VERSION 5.8 ;
NAMESCASESENSITIVE ON ;
BUSBITCHARS "[]" ;
DIVIDERCHAR "/" ;
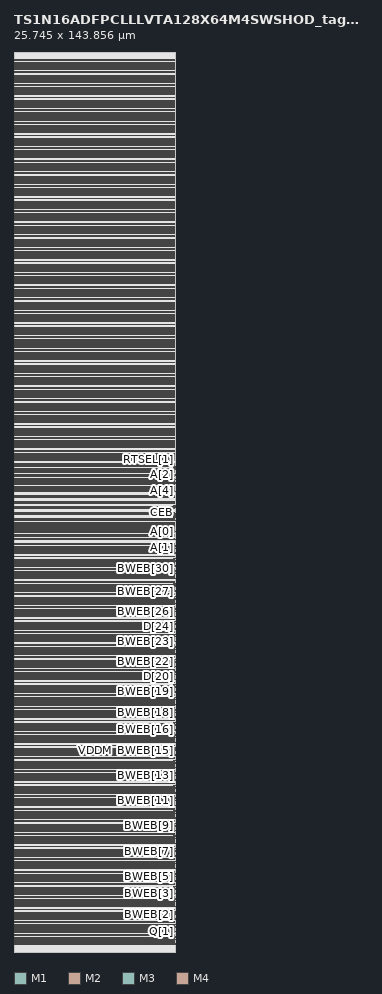
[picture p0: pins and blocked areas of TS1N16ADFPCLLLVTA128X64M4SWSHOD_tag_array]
MACRO TS1N16ADFPCLLLVTA128X64M4SWSHOD_tag_array
	CLASS BLOCK ;
	FOREIGN TS1N16ADFPCLLLVTA128X64M4SWSHOD_tag_array 0.0 0.0 ;
	ORIGIN 0.0 0.0 ;
	SIZE 25.745 BY 143.856 ;
	SYMMETRY X Y ;
	PIN A[0]
		DIRECTION INPUT ;
		USE SIGNAL ;
		PORT
			LAYER M1 ;
			RECT 25.497 67.208 25.745 67.288 ;
			LAYER M2 ;
			RECT 25.497 67.208 25.745 67.288 ;
			LAYER M3 ;
			RECT 25.497 67.208 25.745 67.288 ;
		END
	END A[0]

	PIN A[1]
		DIRECTION INPUT ;
		USE SIGNAL ;
		PORT
			LAYER M1 ;
			RECT 25.497 65.864 25.745 65.944 ;
			LAYER M2 ;
			RECT 25.497 65.864 25.745 65.944 ;
			LAYER M3 ;
			RECT 25.497 65.864 25.745 65.944 ;
		END
	END A[1]

	PIN A[2]
		DIRECTION INPUT ;
		USE SIGNAL ;
		PORT
			LAYER M1 ;
			RECT 25.497 76.232 25.745 76.312 ;
			LAYER M2 ;
			RECT 25.497 76.232 25.745 76.312 ;
			LAYER M3 ;
			RECT 25.497 76.232 25.745 76.312 ;
		END
	END A[2]

	PIN A[3]
		DIRECTION INPUT ;
		USE SIGNAL ;
		PORT
			LAYER M1 ;
			RECT 25.497 75.464 25.745 75.544 ;
			LAYER M2 ;
			RECT 25.497 75.464 25.745 75.544 ;
			LAYER M3 ;
			RECT 25.497 75.464 25.745 75.544 ;
		END
	END A[3]

	PIN A[4]
		DIRECTION INPUT ;
		USE SIGNAL ;
		PORT
			LAYER M1 ;
			RECT 25.497 74.888 25.745 74.968 ;
			LAYER M2 ;
			RECT 25.497 74.888 25.745 74.968 ;
			LAYER M3 ;
			RECT 25.497 74.888 25.745 74.968 ;
		END
	END A[4]



	PIN BWEB[0]
		DIRECTION INPUT ;
		USE SIGNAL ;
		PORT
			LAYER M1 ;
			RECT 25.497 1.976 25.745 2.056 ;
			LAYER M2 ;
			RECT 25.497 1.976 25.745 2.056 ;
			LAYER M3 ;
			RECT 25.497 1.976 25.745 2.056 ;
		END
	END BWEB[0]

	PIN BWEB[1]
		DIRECTION INPUT ;
		USE SIGNAL ;
		PORT
			LAYER M1 ;
			RECT 25.497 3.992 25.745 4.072 ;
			LAYER M2 ;
			RECT 25.497 3.992 25.745 4.072 ;
			LAYER M3 ;
			RECT 25.497 3.992 25.745 4.072 ;
		END
	END BWEB[1]

	PIN BWEB[2]
		DIRECTION INPUT ;
		USE SIGNAL ;
		PORT
			LAYER M1 ;
			RECT 25.497 6.008 25.745 6.088 ;
			LAYER M2 ;
			RECT 25.497 6.008 25.745 6.088 ;
			LAYER M3 ;
			RECT 25.497 6.008 25.745 6.088 ;
		END
	END BWEB[2]

	PIN BWEB[3]
		DIRECTION INPUT ;
		USE SIGNAL ;
		PORT
			LAYER M1 ;
			RECT 25.497 8.024 25.745 8.104 ;
			LAYER M2 ;
			RECT 25.497 8.024 25.745 8.104 ;
			LAYER M3 ;
			RECT 25.497 8.024 25.745 8.104 ;
		END
	END BWEB[3]

	PIN BWEB[4]
		DIRECTION INPUT ;
		USE SIGNAL ;
		PORT
			LAYER M1 ;
			RECT 25.497 10.040 25.745 10.120 ;
			LAYER M2 ;
			RECT 25.497 10.040 25.745 10.120 ;
			LAYER M3 ;
			RECT 25.497 10.040 25.745 10.120 ;
		END
	END BWEB[4]

	PIN BWEB[5]
		DIRECTION INPUT ;
		USE SIGNAL ;
		PORT
			LAYER M1 ;
			RECT 25.497 12.056 25.745 12.136 ;
			LAYER M2 ;
			RECT 25.497 12.056 25.745 12.136 ;
			LAYER M3 ;
			RECT 25.497 12.056 25.745 12.136 ;
		END
	END BWEB[5]

	PIN BWEB[6]
		DIRECTION INPUT ;
		USE SIGNAL ;
		PORT
			LAYER M1 ;
			RECT 25.497 14.072 25.745 14.152 ;
			LAYER M2 ;
			RECT 25.497 14.072 25.745 14.152 ;
			LAYER M3 ;
			RECT 25.497 14.072 25.745 14.152 ;
		END
	END BWEB[6]

	PIN BWEB[7]
		DIRECTION INPUT ;
		USE SIGNAL ;
		PORT
			LAYER M1 ;
			RECT 25.497 16.088 25.745 16.168 ;
			LAYER M2 ;
			RECT 25.497 16.088 25.745 16.168 ;
			LAYER M3 ;
			RECT 25.497 16.088 25.745 16.168 ;
		END
	END BWEB[7]

	PIN BWEB[8]
		DIRECTION INPUT ;
		USE SIGNAL ;
		PORT
			LAYER M1 ;
			RECT 25.497 18.104 25.745 18.184 ;
			LAYER M2 ;
			RECT 25.497 18.104 25.745 18.184 ;
			LAYER M3 ;
			RECT 25.497 18.104 25.745 18.184 ;
		END
	END BWEB[8]

	PIN BWEB[9]
		DIRECTION INPUT ;
		USE SIGNAL ;
		PORT
			LAYER M1 ;
			RECT 25.497 20.120 25.745 20.200 ;
			LAYER M2 ;
			RECT 25.497 20.120 25.745 20.200 ;
			LAYER M3 ;
			RECT 25.497 20.120 25.745 20.200 ;
		END
	END BWEB[9]

	PIN BWEB[10]
		DIRECTION INPUT ;
		USE SIGNAL ;
		PORT
			LAYER M1 ;
			RECT 25.497 22.136 25.745 22.216 ;
			LAYER M2 ;
			RECT 25.497 22.136 25.745 22.216 ;
			LAYER M3 ;
			RECT 25.497 22.136 25.745 22.216 ;
		END
	END BWEB[10]

	PIN BWEB[11]
		DIRECTION INPUT ;
		USE SIGNAL ;
		PORT
			LAYER M1 ;
			RECT 25.497 24.152 25.745 24.232 ;
			LAYER M2 ;
			RECT 25.497 24.152 25.745 24.232 ;
			LAYER M3 ;
			RECT 25.497 24.152 25.745 24.232 ;
		END
	END BWEB[11]

	PIN BWEB[12]
		DIRECTION INPUT ;
		USE SIGNAL ;
		PORT
			LAYER M1 ;
			RECT 25.497 26.168 25.745 26.248 ;
			LAYER M2 ;
			RECT 25.497 26.168 25.745 26.248 ;
			LAYER M3 ;
			RECT 25.497 26.168 25.745 26.248 ;
		END
	END BWEB[12]

	PIN BWEB[13]
		DIRECTION INPUT ;
		USE SIGNAL ;
		PORT
			LAYER M1 ;
			RECT 25.497 28.184 25.745 28.264 ;
			LAYER M2 ;
			RECT 25.497 28.184 25.745 28.264 ;
			LAYER M3 ;
			RECT 25.497 28.184 25.745 28.264 ;
		END
	END BWEB[13]

	PIN BWEB[14]
		DIRECTION INPUT ;
		USE SIGNAL ;
		PORT
			LAYER M1 ;
			RECT 25.497 30.200 25.745 30.280 ;
			LAYER M2 ;
			RECT 25.497 30.200 25.745 30.280 ;
			LAYER M3 ;
			RECT 25.497 30.200 25.745 30.280 ;
		END
	END BWEB[14]

	PIN BWEB[15]
		DIRECTION INPUT ;
		USE SIGNAL ;
		PORT
			LAYER M1 ;
			RECT 25.497 32.216 25.745 32.296 ;
			LAYER M2 ;
			RECT 25.497 32.216 25.745 32.296 ;
			LAYER M3 ;
			RECT 25.497 32.216 25.745 32.296 ;
		END
	END BWEB[15]

	PIN BWEB[16]
		DIRECTION INPUT ;
		USE SIGNAL ;
		PORT
			LAYER M1 ;
			RECT 25.497 34.232 25.745 34.312 ;
			LAYER M2 ;
			RECT 25.497 34.232 25.745 34.312 ;
			LAYER M3 ;
			RECT 25.497 34.232 25.745 34.312 ;
		END
	END BWEB[16]

	PIN BWEB[17]
		DIRECTION INPUT ;
		USE SIGNAL ;
		PORT
			LAYER M1 ;
			RECT 25.497 36.248 25.745 36.328 ;
			LAYER M2 ;
			RECT 25.497 36.248 25.745 36.328 ;
			LAYER M3 ;
			RECT 25.497 36.248 25.745 36.328 ;
		END
	END BWEB[17]

	PIN BWEB[18]
		DIRECTION INPUT ;
		USE SIGNAL ;
		PORT
			LAYER M1 ;
			RECT 25.497 38.264 25.745 38.344 ;
			LAYER M2 ;
			RECT 25.497 38.264 25.745 38.344 ;
			LAYER M3 ;
			RECT 25.497 38.264 25.745 38.344 ;
		END
	END BWEB[18]

	PIN BWEB[19]
		DIRECTION INPUT ;
		USE SIGNAL ;
		PORT
			LAYER M1 ;
			RECT 25.497 40.280 25.745 40.360 ;
			LAYER M2 ;
			RECT 25.497 40.280 25.745 40.360 ;
			LAYER M3 ;
			RECT 25.497 40.280 25.745 40.360 ;
		END
	END BWEB[19]

	PIN BWEB[20]
		DIRECTION INPUT ;
		USE SIGNAL ;
		PORT
			LAYER M1 ;
			RECT 25.497 42.296 25.745 42.376 ;
			LAYER M2 ;
			RECT 25.497 42.296 25.745 42.376 ;
			LAYER M3 ;
			RECT 25.497 42.296 25.745 42.376 ;
		END
	END BWEB[20]

	PIN BWEB[21]
		DIRECTION INPUT ;
		USE SIGNAL ;
		PORT
			LAYER M1 ;
			RECT 25.497 44.312 25.745 44.392 ;
			LAYER M2 ;
			RECT 25.497 44.312 25.745 44.392 ;
			LAYER M3 ;
			RECT 25.497 44.312 25.745 44.392 ;
		END
	END BWEB[21]

	PIN BWEB[22]
		DIRECTION INPUT ;
		USE SIGNAL ;
		PORT
			LAYER M1 ;
			RECT 25.497 46.328 25.745 46.408 ;
			LAYER M2 ;
			RECT 25.497 46.328 25.745 46.408 ;
			LAYER M3 ;
			RECT 25.497 46.328 25.745 46.408 ;
		END
	END BWEB[22]

	PIN BWEB[23]
		DIRECTION INPUT ;
		USE SIGNAL ;
		PORT
			LAYER M1 ;
			RECT 25.497 48.344 25.745 48.424 ;
			LAYER M2 ;
			RECT 25.497 48.344 25.745 48.424 ;
			LAYER M3 ;
			RECT 25.497 48.344 25.745 48.424 ;
		END
	END BWEB[23]

	PIN BWEB[24]
		DIRECTION INPUT ;
		USE SIGNAL ;
		PORT
			LAYER M1 ;
			RECT 25.497 50.360 25.745 50.440 ;
			LAYER M2 ;
			RECT 25.497 50.360 25.745 50.440 ;
			LAYER M3 ;
			RECT 25.497 50.360 25.745 50.440 ;
		END
	END BWEB[24]

	PIN BWEB[25]
		DIRECTION INPUT ;
		USE SIGNAL ;
		PORT
			LAYER M1 ;
			RECT 25.497 52.376 25.745 52.456 ;
			LAYER M2 ;
			RECT 25.497 52.376 25.745 52.456 ;
			LAYER M3 ;
			RECT 25.497 52.376 25.745 52.456 ;
		END
	END BWEB[25]

	PIN BWEB[26]
		DIRECTION INPUT ;
		USE SIGNAL ;
		PORT
			LAYER M1 ;
			RECT 25.497 54.392 25.745 54.472 ;
			LAYER M2 ;
			RECT 25.497 54.392 25.745 54.472 ;
			LAYER M3 ;
			RECT 25.497 54.392 25.745 54.472 ;
		END
	END BWEB[26]

	PIN BWEB[27]
		DIRECTION INPUT ;
		USE SIGNAL ;
		PORT
			LAYER M1 ;
			RECT 25.497 56.408 25.745 56.488 ;
			LAYER M2 ;
			RECT 25.497 56.408 25.745 56.488 ;
			LAYER M3 ;
			RECT 25.497 56.408 25.745 56.488 ;
		END
	END BWEB[27]

	PIN BWEB[28]
		DIRECTION INPUT ;
		USE SIGNAL ;
		PORT
			LAYER M1 ;
			RECT 25.497 58.424 25.745 58.504 ;
			LAYER M2 ;
			RECT 25.497 58.424 25.745 58.504 ;
			LAYER M3 ;
			RECT 25.497 58.424 25.745 58.504 ;
		END
	END BWEB[28]

	PIN BWEB[29]
		DIRECTION INPUT ;
		USE SIGNAL ;
		PORT
			LAYER M1 ;
			RECT 25.497 60.440 25.745 60.520 ;
			LAYER M2 ;
			RECT 25.497 60.440 25.745 60.520 ;
			LAYER M3 ;
			RECT 25.497 60.440 25.745 60.520 ;
		END
	END BWEB[29]

	PIN BWEB[30]
		DIRECTION INPUT ;
		USE SIGNAL ;
		PORT
			LAYER M1 ;
			RECT 25.497 62.456 25.745 62.536 ;
			LAYER M2 ;
			RECT 25.497 62.456 25.745 62.536 ;
			LAYER M3 ;
			RECT 25.497 62.456 25.745 62.536 ;
		END
	END BWEB[30]

	PIN BWEB[31]
		DIRECTION INPUT ;
		USE SIGNAL ;
		PORT
			LAYER M1 ;
			RECT 25.497 64.472 25.745 64.552 ;
			LAYER M2 ;
			RECT 25.497 64.472 25.745 64.552 ;
			LAYER M3 ;
			RECT 25.497 64.472 25.745 64.552 ;
		END
	END BWEB[31]

































	PIN CEB
		DIRECTION INPUT ;
		USE SIGNAL ;
		PORT
			LAYER M1 ;
			RECT 25.497 68.936 25.745 69.016 ;
			LAYER M2 ;
			RECT 25.497 68.936 25.745 69.016 ;
			LAYER M3 ;
			RECT 25.497 68.936 25.745 69.016 ;
		END
	END CEB

	PIN CLK
		DIRECTION INPUT ;
		USE SIGNAL ;
		PORT
			LAYER M1 ;
			RECT 25.497 71.240 25.745 71.320 ;
			LAYER M2 ;
			RECT 25.497 71.240 25.745 71.320 ;
			LAYER M3 ;
			RECT 25.497 71.240 25.745 71.320 ;
		END
	END CLK

	PIN D[0]
		DIRECTION INPUT ;
		USE SIGNAL ;
		PORT
			LAYER M1 ;
			RECT 25.497 2.360 25.745 2.440 ;
			LAYER M2 ;
			RECT 25.497 2.360 25.745 2.440 ;
			LAYER M3 ;
			RECT 25.497 2.360 25.745 2.440 ;
		END
	END D[0]

	PIN D[1]
		DIRECTION INPUT ;
		USE SIGNAL ;
		PORT
			LAYER M1 ;
			RECT 25.497 4.376 25.745 4.456 ;
			LAYER M2 ;
			RECT 25.497 4.376 25.745 4.456 ;
			LAYER M3 ;
			RECT 25.497 4.376 25.745 4.456 ;
		END
	END D[1]

	PIN D[2]
		DIRECTION INPUT ;
		USE SIGNAL ;
		PORT
			LAYER M1 ;
			RECT 25.497 6.392 25.745 6.472 ;
			LAYER M2 ;
			RECT 25.497 6.392 25.745 6.472 ;
			LAYER M3 ;
			RECT 25.497 6.392 25.745 6.472 ;
		END
	END D[2]

	PIN D[3]
		DIRECTION INPUT ;
		USE SIGNAL ;
		PORT
			LAYER M1 ;
			RECT 25.497 8.408 25.745 8.488 ;
			LAYER M2 ;
			RECT 25.497 8.408 25.745 8.488 ;
			LAYER M3 ;
			RECT 25.497 8.408 25.745 8.488 ;
		END
	END D[3]

	PIN D[4]
		DIRECTION INPUT ;
		USE SIGNAL ;
		PORT
			LAYER M1 ;
			RECT 25.497 10.424 25.745 10.504 ;
			LAYER M2 ;
			RECT 25.497 10.424 25.745 10.504 ;
			LAYER M3 ;
			RECT 25.497 10.424 25.745 10.504 ;
		END
	END D[4]

	PIN D[5]
		DIRECTION INPUT ;
		USE SIGNAL ;
		PORT
			LAYER M1 ;
			RECT 25.497 12.440 25.745 12.520 ;
			LAYER M2 ;
			RECT 25.497 12.440 25.745 12.520 ;
			LAYER M3 ;
			RECT 25.497 12.440 25.745 12.520 ;
		END
	END D[5]

	PIN D[6]
		DIRECTION INPUT ;
		USE SIGNAL ;
		PORT
			LAYER M1 ;
			RECT 25.497 14.456 25.745 14.536 ;
			LAYER M2 ;
			RECT 25.497 14.456 25.745 14.536 ;
			LAYER M3 ;
			RECT 25.497 14.456 25.745 14.536 ;
		END
	END D[6]

	PIN D[7]
		DIRECTION INPUT ;
		USE SIGNAL ;
		PORT
			LAYER M1 ;
			RECT 25.497 16.472 25.745 16.552 ;
			LAYER M2 ;
			RECT 25.497 16.472 25.745 16.552 ;
			LAYER M3 ;
			RECT 25.497 16.472 25.745 16.552 ;
		END
	END D[7]

	PIN D[8]
		DIRECTION INPUT ;
		USE SIGNAL ;
		PORT
			LAYER M1 ;
			RECT 25.497 18.488 25.745 18.568 ;
			LAYER M2 ;
			RECT 25.497 18.488 25.745 18.568 ;
			LAYER M3 ;
			RECT 25.497 18.488 25.745 18.568 ;
		END
	END D[8]

	PIN D[9]
		DIRECTION INPUT ;
		USE SIGNAL ;
		PORT
			LAYER M1 ;
			RECT 25.497 20.504 25.745 20.584 ;
			LAYER M2 ;
			RECT 25.497 20.504 25.745 20.584 ;
			LAYER M3 ;
			RECT 25.497 20.504 25.745 20.584 ;
		END
	END D[9]

	PIN D[10]
		DIRECTION INPUT ;
		USE SIGNAL ;
		PORT
			LAYER M1 ;
			RECT 25.497 22.520 25.745 22.600 ;
			LAYER M2 ;
			RECT 25.497 22.520 25.745 22.600 ;
			LAYER M3 ;
			RECT 25.497 22.520 25.745 22.600 ;
		END
	END D[10]

	PIN D[11]
		DIRECTION INPUT ;
		USE SIGNAL ;
		PORT
			LAYER M1 ;
			RECT 25.497 24.536 25.745 24.616 ;
			LAYER M2 ;
			RECT 25.497 24.536 25.745 24.616 ;
			LAYER M3 ;
			RECT 25.497 24.536 25.745 24.616 ;
		END
	END D[11]

	PIN D[12]
		DIRECTION INPUT ;
		USE SIGNAL ;
		PORT
			LAYER M1 ;
			RECT 25.497 26.552 25.745 26.632 ;
			LAYER M2 ;
			RECT 25.497 26.552 25.745 26.632 ;
			LAYER M3 ;
			RECT 25.497 26.552 25.745 26.632 ;
		END
	END D[12]

	PIN D[13]
		DIRECTION INPUT ;
		USE SIGNAL ;
		PORT
			LAYER M1 ;
			RECT 25.497 28.568 25.745 28.648 ;
			LAYER M2 ;
			RECT 25.497 28.568 25.745 28.648 ;
			LAYER M3 ;
			RECT 25.497 28.568 25.745 28.648 ;
		END
	END D[13]

	PIN D[14]
		DIRECTION INPUT ;
		USE SIGNAL ;
		PORT
			LAYER M1 ;
			RECT 25.497 30.584 25.745 30.664 ;
			LAYER M2 ;
			RECT 25.497 30.584 25.745 30.664 ;
			LAYER M3 ;
			RECT 25.497 30.584 25.745 30.664 ;
		END
	END D[14]

	PIN D[15]
		DIRECTION INPUT ;
		USE SIGNAL ;
		PORT
			LAYER M1 ;
			RECT 25.497 32.600 25.745 32.680 ;
			LAYER M2 ;
			RECT 25.497 32.600 25.745 32.680 ;
			LAYER M3 ;
			RECT 25.497 32.600 25.745 32.680 ;
		END
	END D[15]

	PIN D[16]
		DIRECTION INPUT ;
		USE SIGNAL ;
		PORT
			LAYER M1 ;
			RECT 25.497 34.616 25.745 34.696 ;
			LAYER M2 ;
			RECT 25.497 34.616 25.745 34.696 ;
			LAYER M3 ;
			RECT 25.497 34.616 25.745 34.696 ;
		END
	END D[16]

	PIN D[17]
		DIRECTION INPUT ;
		USE SIGNAL ;
		PORT
			LAYER M1 ;
			RECT 25.497 36.632 25.745 36.712 ;
			LAYER M2 ;
			RECT 25.497 36.632 25.745 36.712 ;
			LAYER M3 ;
			RECT 25.497 36.632 25.745 36.712 ;
		END
	END D[17]

	PIN D[18]
		DIRECTION INPUT ;
		USE SIGNAL ;
		PORT
			LAYER M1 ;
			RECT 25.497 38.648 25.745 38.728 ;
			LAYER M2 ;
			RECT 25.497 38.648 25.745 38.728 ;
			LAYER M3 ;
			RECT 25.497 38.648 25.745 38.728 ;
		END
	END D[18]

	PIN D[19]
		DIRECTION INPUT ;
		USE SIGNAL ;
		PORT
			LAYER M1 ;
			RECT 25.497 40.664 25.745 40.744 ;
			LAYER M2 ;
			RECT 25.497 40.664 25.745 40.744 ;
			LAYER M3 ;
			RECT 25.497 40.664 25.745 40.744 ;
		END
	END D[19]

	PIN D[20]
		DIRECTION INPUT ;
		USE SIGNAL ;
		PORT
			LAYER M1 ;
			RECT 25.497 42.680 25.745 42.760 ;
			LAYER M2 ;
			RECT 25.497 42.680 25.745 42.760 ;
			LAYER M3 ;
			RECT 25.497 42.680 25.745 42.760 ;
		END
	END D[20]

	PIN D[21]
		DIRECTION INPUT ;
		USE SIGNAL ;
		PORT
			LAYER M1 ;
			RECT 25.497 44.696 25.745 44.776 ;
			LAYER M2 ;
			RECT 25.497 44.696 25.745 44.776 ;
			LAYER M3 ;
			RECT 25.497 44.696 25.745 44.776 ;
		END
	END D[21]

	PIN D[22]
		DIRECTION INPUT ;
		USE SIGNAL ;
		PORT
			LAYER M1 ;
			RECT 25.497 46.712 25.745 46.792 ;
			LAYER M2 ;
			RECT 25.497 46.712 25.745 46.792 ;
			LAYER M3 ;
			RECT 25.497 46.712 25.745 46.792 ;
		END
	END D[22]

	PIN D[23]
		DIRECTION INPUT ;
		USE SIGNAL ;
		PORT
			LAYER M1 ;
			RECT 25.497 48.728 25.745 48.808 ;
			LAYER M2 ;
			RECT 25.497 48.728 25.745 48.808 ;
			LAYER M3 ;
			RECT 25.497 48.728 25.745 48.808 ;
		END
	END D[23]

	PIN D[24]
		DIRECTION INPUT ;
		USE SIGNAL ;
		PORT
			LAYER M1 ;
			RECT 25.497 50.744 25.745 50.824 ;
			LAYER M2 ;
			RECT 25.497 50.744 25.745 50.824 ;
			LAYER M3 ;
			RECT 25.497 50.744 25.745 50.824 ;
		END
	END D[24]

	PIN D[25]
		DIRECTION INPUT ;
		USE SIGNAL ;
		PORT
			LAYER M1 ;
			RECT 25.497 52.760 25.745 52.840 ;
			LAYER M2 ;
			RECT 25.497 52.760 25.745 52.840 ;
			LAYER M3 ;
			RECT 25.497 52.760 25.745 52.840 ;
		END
	END D[25]

	PIN D[26]
		DIRECTION INPUT ;
		USE SIGNAL ;
		PORT
			LAYER M1 ;
			RECT 25.497 54.776 25.745 54.856 ;
			LAYER M2 ;
			RECT 25.497 54.776 25.745 54.856 ;
			LAYER M3 ;
			RECT 25.497 54.776 25.745 54.856 ;
		END
	END D[26]

	PIN D[27]
		DIRECTION INPUT ;
		USE SIGNAL ;
		PORT
			LAYER M1 ;
			RECT 25.497 56.792 25.745 56.872 ;
			LAYER M2 ;
			RECT 25.497 56.792 25.745 56.872 ;
			LAYER M3 ;
			RECT 25.497 56.792 25.745 56.872 ;
		END
	END D[27]

	PIN D[28]
		DIRECTION INPUT ;
		USE SIGNAL ;
		PORT
			LAYER M1 ;
			RECT 25.497 58.808 25.745 58.888 ;
			LAYER M2 ;
			RECT 25.497 58.808 25.745 58.888 ;
			LAYER M3 ;
			RECT 25.497 58.808 25.745 58.888 ;
		END
	END D[28]

	PIN D[29]
		DIRECTION INPUT ;
		USE SIGNAL ;
		PORT
			LAYER M1 ;
			RECT 25.497 60.824 25.745 60.904 ;
			LAYER M2 ;
			RECT 25.497 60.824 25.745 60.904 ;
			LAYER M3 ;
			RECT 25.497 60.824 25.745 60.904 ;
		END
	END D[29]

	PIN D[30]
		DIRECTION INPUT ;
		USE SIGNAL ;
		PORT
			LAYER M1 ;
			RECT 25.497 62.840 25.745 62.920 ;
			LAYER M2 ;
			RECT 25.497 62.840 25.745 62.920 ;
			LAYER M3 ;
			RECT 25.497 62.840 25.745 62.920 ;
		END
	END D[30]

	PIN D[31]
		DIRECTION INPUT ;
		USE SIGNAL ;
		PORT
			LAYER M1 ;
			RECT 25.497 64.856 25.745 64.936 ;
			LAYER M2 ;
			RECT 25.497 64.856 25.745 64.936 ;
			LAYER M3 ;
			RECT 25.497 64.856 25.745 64.936 ;
		END
	END D[31]

































	PIN DSLP
		DIRECTION INPUT ;
		USE SIGNAL ;
		PORT
			LAYER M1 ;
			RECT 25.497 69.512 25.745 69.592 ;
			LAYER M2 ;
			RECT 25.497 69.512 25.745 69.592 ;
			LAYER M3 ;
			RECT 25.497 69.512 25.745 69.592 ;
		END
	END DSLP

	PIN PUDELAY
		DIRECTION OUTPUT ;
		USE SIGNAL ;
		PORT
			LAYER M1 ;
			RECT 25.497 77.576 25.745 77.656 ;
			LAYER M2 ;
			RECT 25.497 77.576 25.745 77.656 ;
			LAYER M3 ;
			RECT 25.497 77.576 25.745 77.656 ;
		END
	END PUDELAY

	PIN Q[0]
		DIRECTION OUTPUT ;
		USE SIGNAL ;
		PORT
			LAYER M1 ;
			RECT 25.497 1.208 25.745 1.288 ;
			LAYER M2 ;
			RECT 25.497 1.208 25.745 1.288 ;
			LAYER M3 ;
			RECT 25.497 1.208 25.745 1.288 ;
		END
	END Q[0]

	PIN Q[1]
		DIRECTION OUTPUT ;
		USE SIGNAL ;
		PORT
			LAYER M1 ;
			RECT 25.497 3.224 25.745 3.304 ;
			LAYER M2 ;
			RECT 25.497 3.224 25.745 3.304 ;
			LAYER M3 ;
			RECT 25.497 3.224 25.745 3.304 ;
		END
	END Q[1]

	PIN Q[2]
		DIRECTION OUTPUT ;
		USE SIGNAL ;
		PORT
			LAYER M1 ;
			RECT 25.497 5.240 25.745 5.320 ;
			LAYER M2 ;
			RECT 25.497 5.240 25.745 5.320 ;
			LAYER M3 ;
			RECT 25.497 5.240 25.745 5.320 ;
		END
	END Q[2]

	PIN Q[3]
		DIRECTION OUTPUT ;
		USE SIGNAL ;
		PORT
			LAYER M1 ;
			RECT 25.497 7.256 25.745 7.336 ;
			LAYER M2 ;
			RECT 25.497 7.256 25.745 7.336 ;
			LAYER M3 ;
			RECT 25.497 7.256 25.745 7.336 ;
		END
	END Q[3]

	PIN Q[4]
		DIRECTION OUTPUT ;
		USE SIGNAL ;
		PORT
			LAYER M1 ;
			RECT 25.497 9.272 25.745 9.352 ;
			LAYER M2 ;
			RECT 25.497 9.272 25.745 9.352 ;
			LAYER M3 ;
			RECT 25.497 9.272 25.745 9.352 ;
		END
	END Q[4]

	PIN Q[5]
		DIRECTION OUTPUT ;
		USE SIGNAL ;
		PORT
			LAYER M1 ;
			RECT 25.497 11.288 25.745 11.368 ;
			LAYER M2 ;
			RECT 25.497 11.288 25.745 11.368 ;
			LAYER M3 ;
			RECT 25.497 11.288 25.745 11.368 ;
		END
	END Q[5]

	PIN Q[6]
		DIRECTION OUTPUT ;
		USE SIGNAL ;
		PORT
			LAYER M1 ;
			RECT 25.497 13.304 25.745 13.384 ;
			LAYER M2 ;
			RECT 25.497 13.304 25.745 13.384 ;
			LAYER M3 ;
			RECT 25.497 13.304 25.745 13.384 ;
		END
	END Q[6]

	PIN Q[7]
		DIRECTION OUTPUT ;
		USE SIGNAL ;
		PORT
			LAYER M1 ;
			RECT 25.497 15.320 25.745 15.400 ;
			LAYER M2 ;
			RECT 25.497 15.320 25.745 15.400 ;
			LAYER M3 ;
			RECT 25.497 15.320 25.745 15.400 ;
		END
	END Q[7]

	PIN Q[8]
		DIRECTION OUTPUT ;
		USE SIGNAL ;
		PORT
			LAYER M1 ;
			RECT 25.497 17.336 25.745 17.416 ;
			LAYER M2 ;
			RECT 25.497 17.336 25.745 17.416 ;
			LAYER M3 ;
			RECT 25.497 17.336 25.745 17.416 ;
		END
	END Q[8]

	PIN Q[9]
		DIRECTION OUTPUT ;
		USE SIGNAL ;
		PORT
			LAYER M1 ;
			RECT 25.497 19.352 25.745 19.432 ;
			LAYER M2 ;
			RECT 25.497 19.352 25.745 19.432 ;
			LAYER M3 ;
			RECT 25.497 19.352 25.745 19.432 ;
		END
	END Q[9]

	PIN Q[10]
		DIRECTION OUTPUT ;
		USE SIGNAL ;
		PORT
			LAYER M1 ;
			RECT 25.497 21.368 25.745 21.448 ;
			LAYER M2 ;
			RECT 25.497 21.368 25.745 21.448 ;
			LAYER M3 ;
			RECT 25.497 21.368 25.745 21.448 ;
		END
	END Q[10]

	PIN Q[11]
		DIRECTION OUTPUT ;
		USE SIGNAL ;
		PORT
			LAYER M1 ;
			RECT 25.497 23.384 25.745 23.464 ;
			LAYER M2 ;
			RECT 25.497 23.384 25.745 23.464 ;
			LAYER M3 ;
			RECT 25.497 23.384 25.745 23.464 ;
		END
	END Q[11]

	PIN Q[12]
		DIRECTION OUTPUT ;
		USE SIGNAL ;
		PORT
			LAYER M1 ;
			RECT 25.497 25.400 25.745 25.480 ;
			LAYER M2 ;
			RECT 25.497 25.400 25.745 25.480 ;
			LAYER M3 ;
			RECT 25.497 25.400 25.745 25.480 ;
		END
	END Q[12]

	PIN Q[13]
		DIRECTION OUTPUT ;
		USE SIGNAL ;
		PORT
			LAYER M1 ;
			RECT 25.497 27.416 25.745 27.496 ;
			LAYER M2 ;
			RECT 25.497 27.416 25.745 27.496 ;
			LAYER M3 ;
			RECT 25.497 27.416 25.745 27.496 ;
		END
	END Q[13]

	PIN Q[14]
		DIRECTION OUTPUT ;
		USE SIGNAL ;
		PORT
			LAYER M1 ;
			RECT 25.497 29.432 25.745 29.512 ;
			LAYER M2 ;
			RECT 25.497 29.432 25.745 29.512 ;
			LAYER M3 ;
			RECT 25.497 29.432 25.745 29.512 ;
		END
	END Q[14]

	PIN Q[15]
		DIRECTION OUTPUT ;
		USE SIGNAL ;
		PORT
			LAYER M1 ;
			RECT 25.497 31.448 25.745 31.528 ;
			LAYER M2 ;
			RECT 25.497 31.448 25.745 31.528 ;
			LAYER M3 ;
			RECT 25.497 31.448 25.745 31.528 ;
		END
	END Q[15]

	PIN Q[16]
		DIRECTION OUTPUT ;
		USE SIGNAL ;
		PORT
			LAYER M1 ;
			RECT 25.497 33.464 25.745 33.544 ;
			LAYER M2 ;
			RECT 25.497 33.464 25.745 33.544 ;
			LAYER M3 ;
			RECT 25.497 33.464 25.745 33.544 ;
		END
	END Q[16]

	PIN Q[17]
		DIRECTION OUTPUT ;
		USE SIGNAL ;
		PORT
			LAYER M1 ;
			RECT 25.497 35.480 25.745 35.560 ;
			LAYER M2 ;
			RECT 25.497 35.480 25.745 35.560 ;
			LAYER M3 ;
			RECT 25.497 35.480 25.745 35.560 ;
		END
	END Q[17]

	PIN Q[18]
		DIRECTION OUTPUT ;
		USE SIGNAL ;
		PORT
			LAYER M1 ;
			RECT 25.497 37.496 25.745 37.576 ;
			LAYER M2 ;
			RECT 25.497 37.496 25.745 37.576 ;
			LAYER M3 ;
			RECT 25.497 37.496 25.745 37.576 ;
		END
	END Q[18]

	PIN Q[19]
		DIRECTION OUTPUT ;
		USE SIGNAL ;
		PORT
			LAYER M1 ;
			RECT 25.497 39.512 25.745 39.592 ;
			LAYER M2 ;
			RECT 25.497 39.512 25.745 39.592 ;
			LAYER M3 ;
			RECT 25.497 39.512 25.745 39.592 ;
		END
	END Q[19]

	PIN Q[20]
		DIRECTION OUTPUT ;
		USE SIGNAL ;
		PORT
			LAYER M1 ;
			RECT 25.497 41.528 25.745 41.608 ;
			LAYER M2 ;
			RECT 25.497 41.528 25.745 41.608 ;
			LAYER M3 ;
			RECT 25.497 41.528 25.745 41.608 ;
		END
	END Q[20]

	PIN Q[21]
		DIRECTION OUTPUT ;
		USE SIGNAL ;
		PORT
			LAYER M1 ;
			RECT 25.497 43.544 25.745 43.624 ;
			LAYER M2 ;
			RECT 25.497 43.544 25.745 43.624 ;
			LAYER M3 ;
			RECT 25.497 43.544 25.745 43.624 ;
		END
	END Q[21]

	PIN Q[22]
		DIRECTION OUTPUT ;
		USE SIGNAL ;
		PORT
			LAYER M1 ;
			RECT 25.497 45.560 25.745 45.640 ;
			LAYER M2 ;
			RECT 25.497 45.560 25.745 45.640 ;
			LAYER M3 ;
			RECT 25.497 45.560 25.745 45.640 ;
		END
	END Q[22]

	PIN Q[23]
		DIRECTION OUTPUT ;
		USE SIGNAL ;
		PORT
			LAYER M1 ;
			RECT 25.497 47.576 25.745 47.656 ;
			LAYER M2 ;
			RECT 25.497 47.576 25.745 47.656 ;
			LAYER M3 ;
			RECT 25.497 47.576 25.745 47.656 ;
		END
	END Q[23]

	PIN Q[24]
		DIRECTION OUTPUT ;
		USE SIGNAL ;
		PORT
			LAYER M1 ;
			RECT 25.497 49.592 25.745 49.672 ;
			LAYER M2 ;
			RECT 25.497 49.592 25.745 49.672 ;
			LAYER M3 ;
			RECT 25.497 49.592 25.745 49.672 ;
		END
	END Q[24]

	PIN Q[25]
		DIRECTION OUTPUT ;
		USE SIGNAL ;
		PORT
			LAYER M1 ;
			RECT 25.497 51.608 25.745 51.688 ;
			LAYER M2 ;
			RECT 25.497 51.608 25.745 51.688 ;
			LAYER M3 ;
			RECT 25.497 51.608 25.745 51.688 ;
		END
	END Q[25]

	PIN Q[26]
		DIRECTION OUTPUT ;
		USE SIGNAL ;
		PORT
			LAYER M1 ;
			RECT 25.497 53.624 25.745 53.704 ;
			LAYER M2 ;
			RECT 25.497 53.624 25.745 53.704 ;
			LAYER M3 ;
			RECT 25.497 53.624 25.745 53.704 ;
		END
	END Q[26]

	PIN Q[27]
		DIRECTION OUTPUT ;
		USE SIGNAL ;
		PORT
			LAYER M1 ;
			RECT 25.497 55.640 25.745 55.720 ;
			LAYER M2 ;
			RECT 25.497 55.640 25.745 55.720 ;
			LAYER M3 ;
			RECT 25.497 55.640 25.745 55.720 ;
		END
	END Q[27]

	PIN Q[28]
		DIRECTION OUTPUT ;
		USE SIGNAL ;
		PORT
			LAYER M1 ;
			RECT 25.497 57.656 25.745 57.736 ;
			LAYER M2 ;
			RECT 25.497 57.656 25.745 57.736 ;
			LAYER M3 ;
			RECT 25.497 57.656 25.745 57.736 ;
		END
	END Q[28]

	PIN Q[29]
		DIRECTION OUTPUT ;
		USE SIGNAL ;
		PORT
			LAYER M1 ;
			RECT 25.497 59.672 25.745 59.752 ;
			LAYER M2 ;
			RECT 25.497 59.672 25.745 59.752 ;
			LAYER M3 ;
			RECT 25.497 59.672 25.745 59.752 ;
		END
	END Q[29]

	PIN Q[30]
		DIRECTION OUTPUT ;
		USE SIGNAL ;
		PORT
			LAYER M1 ;
			RECT 25.497 61.688 25.745 61.768 ;
			LAYER M2 ;
			RECT 25.497 61.688 25.745 61.768 ;
			LAYER M3 ;
			RECT 25.497 61.688 25.745 61.768 ;
		END
	END Q[30]

	PIN Q[31]
		DIRECTION OUTPUT ;
		USE SIGNAL ;
		PORT
			LAYER M1 ;
			RECT 25.497 63.704 25.745 63.784 ;
			LAYER M2 ;
			RECT 25.497 63.704 25.745 63.784 ;
			LAYER M3 ;
			RECT 25.497 63.704 25.745 63.784 ;
		END
	END Q[31]

































	PIN RTSEL[0]
		DIRECTION INPUT ;
		USE SIGNAL ;
		PORT
			LAYER M1 ;
			RECT 25.497 77.192 25.745 77.272 ;
			LAYER M2 ;
			RECT 25.497 77.192 25.745 77.272 ;
			LAYER M3 ;
			RECT 25.497 77.192 25.745 77.272 ;
		END
	END RTSEL[0]

	PIN RTSEL[1]
		DIRECTION INPUT ;
		USE SIGNAL ;
		PORT
			LAYER M1 ;
			RECT 25.497 77.384 25.745 77.464 ;
			LAYER M2 ;
			RECT 25.497 77.384 25.745 77.464 ;
			LAYER M3 ;
			RECT 25.497 77.384 25.745 77.464 ;
		END
	END RTSEL[1]

	PIN SD
		DIRECTION INPUT ;
		USE SIGNAL ;
		PORT
			LAYER M1 ;
			RECT 25.497 73.544 25.745 73.624 ;
			LAYER M2 ;
			RECT 25.497 73.544 25.745 73.624 ;
			LAYER M3 ;
			RECT 25.497 73.544 25.745 73.624 ;
		END
	END SD

	PIN SLP
		DIRECTION INPUT ;
		USE SIGNAL ;
		PORT
			LAYER M1 ;
			RECT 25.497 69.704 25.745 69.784 ;
			LAYER M2 ;
			RECT 25.497 69.704 25.745 69.784 ;
			LAYER M3 ;
			RECT 25.497 69.704 25.745 69.784 ;
		END
	END SLP

	PIN VDD
		DIRECTION INOUT ;
		USE POWER ;
		PORT
			LAYER M4 ;
			RECT 20.493 1.428 25.625 1.548 ;
			LAYER M4 ;
			RECT 20.493 3.444 25.625 3.564 ;
			LAYER M4 ;
			RECT 20.493 5.460 25.625 5.580 ;
			LAYER M4 ;
			RECT 20.493 7.476 25.625 7.596 ;
			LAYER M4 ;
			RECT 20.493 9.492 25.625 9.612 ;
			LAYER M4 ;
			RECT 20.493 11.508 25.625 11.628 ;
			LAYER M4 ;
			RECT 20.493 13.524 25.625 13.644 ;
			LAYER M4 ;
			RECT 20.493 15.540 25.625 15.660 ;
			LAYER M4 ;
			RECT 20.493 17.556 25.625 17.676 ;
			LAYER M4 ;
			RECT 20.493 19.572 25.625 19.692 ;
			LAYER M4 ;
			RECT 20.493 21.588 25.625 21.708 ;
			LAYER M4 ;
			RECT 20.493 23.604 25.625 23.724 ;
			LAYER M4 ;
			RECT 20.493 25.620 25.625 25.740 ;
			LAYER M4 ;
			RECT 20.493 27.636 25.625 27.756 ;
			LAYER M4 ;
			RECT 20.493 29.652 25.625 29.772 ;
			LAYER M4 ;
			RECT 20.493 31.668 25.625 31.788 ;
			LAYER M4 ;
			RECT 20.493 33.684 25.625 33.804 ;
			LAYER M4 ;
			RECT 20.493 35.700 25.625 35.820 ;
			LAYER M4 ;
			RECT 20.493 37.716 25.625 37.836 ;
			LAYER M4 ;
			RECT 20.493 39.732 25.625 39.852 ;
			LAYER M4 ;
			RECT 20.493 41.748 25.625 41.868 ;
			LAYER M4 ;
			RECT 20.493 43.764 25.625 43.884 ;
			LAYER M4 ;
			RECT 20.493 45.780 25.625 45.900 ;
			LAYER M4 ;
			RECT 20.493 47.796 25.625 47.916 ;
			LAYER M4 ;
			RECT 20.493 49.812 25.625 49.932 ;
			LAYER M4 ;
			RECT 20.493 51.828 25.625 51.948 ;
			LAYER M4 ;
			RECT 20.493 53.844 25.625 53.964 ;
			LAYER M4 ;
			RECT 20.493 55.860 25.625 55.980 ;
			LAYER M4 ;
			RECT 20.493 57.876 25.625 57.996 ;
			LAYER M4 ;
			RECT 20.493 59.892 25.625 60.012 ;
			LAYER M4 ;
			RECT 20.493 61.908 25.625 62.028 ;
			LAYER M4 ;
			RECT 20.493 63.924 25.625 64.044 ;
			LAYER M4 ;
			RECT 20.493 66.580 25.625 66.700 ;
			LAYER M4 ;
			RECT 20.493 67.906 25.625 68.026 ;
			LAYER M4 ;
			RECT 20.493 70.138 25.625 70.258 ;
			LAYER M4 ;
			RECT 20.493 71.732 25.625 71.852 ;
			LAYER M4 ;
			RECT 20.493 74.936 25.625 75.056 ;
			LAYER M4 ;
			RECT 20.493 77.158 25.625 77.278 ;
			LAYER M4 ;
			RECT 20.493 78.804 25.625 78.924 ;
			LAYER M4 ;
			RECT 20.493 80.820 25.625 80.940 ;
			LAYER M4 ;
			RECT 20.493 82.836 25.625 82.956 ;
			LAYER M4 ;
			RECT 20.493 84.852 25.625 84.972 ;
			LAYER M4 ;
			RECT 20.493 86.868 25.625 86.988 ;
			LAYER M4 ;
			RECT 20.493 88.884 25.625 89.004 ;
			LAYER M4 ;
			RECT 20.493 90.900 25.625 91.020 ;
			LAYER M4 ;
			RECT 20.493 92.916 25.625 93.036 ;
			LAYER M4 ;
			RECT 20.493 94.932 25.625 95.052 ;
			LAYER M4 ;
			RECT 20.493 96.948 25.625 97.068 ;
			LAYER M4 ;
			RECT 20.493 98.964 25.625 99.084 ;
			LAYER M4 ;
			RECT 20.493 100.980 25.625 101.100 ;
			LAYER M4 ;
			RECT 20.493 102.996 25.625 103.116 ;
			LAYER M4 ;
			RECT 20.493 105.012 25.625 105.132 ;
			LAYER M4 ;
			RECT 20.493 107.028 25.625 107.148 ;
			LAYER M4 ;
			RECT 20.493 109.044 25.625 109.164 ;
			LAYER M4 ;
			RECT 20.493 111.060 25.625 111.180 ;
			LAYER M4 ;
			RECT 20.493 113.076 25.625 113.196 ;
			LAYER M4 ;
			RECT 20.493 115.092 25.625 115.212 ;
			LAYER M4 ;
			RECT 20.493 117.108 25.625 117.228 ;
			LAYER M4 ;
			RECT 20.493 119.124 25.625 119.244 ;
			LAYER M4 ;
			RECT 20.493 121.140 25.625 121.260 ;
			LAYER M4 ;
			RECT 20.493 123.156 25.625 123.276 ;
			LAYER M4 ;
			RECT 20.493 125.172 25.625 125.292 ;
			LAYER M4 ;
			RECT 20.493 127.188 25.625 127.308 ;
			LAYER M4 ;
			RECT 20.493 129.204 25.625 129.324 ;
			LAYER M4 ;
			RECT 20.493 131.220 25.625 131.340 ;
			LAYER M4 ;
			RECT 20.493 133.236 25.625 133.356 ;
			LAYER M4 ;
			RECT 20.493 135.252 25.625 135.372 ;
			LAYER M4 ;
			RECT 20.493 137.268 25.625 137.388 ;
			LAYER M4 ;
			RECT 20.493 139.284 25.625 139.404 ;
			LAYER M4 ;
			RECT 20.493 141.300 25.625 141.420 ;
		END
	END VDD

	PIN VDDM
		DIRECTION INOUT ;
		USE POWER ;
		PORT
			LAYER M4 ;
			RECT 0.120 1.428 20.343 1.548 ;
			LAYER M4 ;
			RECT 0.120 1.932 25.625 2.052 ;
			LAYER M4 ;
			RECT 0.120 2.184 25.625 2.304 ;
			LAYER M4 ;
			RECT 0.120 3.444 20.343 3.564 ;
			LAYER M4 ;
			RECT 0.120 3.948 25.625 4.068 ;
			LAYER M4 ;
			RECT 0.120 4.200 25.625 4.320 ;
			LAYER M4 ;
			RECT 0.120 5.460 20.343 5.580 ;
			LAYER M4 ;
			RECT 0.120 5.964 25.625 6.084 ;
			LAYER M4 ;
			RECT 0.120 6.216 25.625 6.336 ;
			LAYER M4 ;
			RECT 0.120 7.476 20.343 7.596 ;
			LAYER M4 ;
			RECT 0.120 7.980 25.625 8.100 ;
			LAYER M4 ;
			RECT 0.120 8.232 25.625 8.352 ;
			LAYER M4 ;
			RECT 0.120 9.492 20.343 9.612 ;
			LAYER M4 ;
			RECT 0.120 9.996 25.625 10.116 ;
			LAYER M4 ;
			RECT 0.120 10.248 25.625 10.368 ;
			LAYER M4 ;
			RECT 0.120 11.508 20.343 11.628 ;
			LAYER M4 ;
			RECT 0.120 12.012 25.625 12.132 ;
			LAYER M4 ;
			RECT 0.120 12.264 25.625 12.384 ;
			LAYER M4 ;
			RECT 0.120 13.524 20.343 13.644 ;
			LAYER M4 ;
			RECT 0.120 14.028 25.625 14.148 ;
			LAYER M4 ;
			RECT 0.120 14.280 25.625 14.400 ;
			LAYER M4 ;
			RECT 0.120 15.540 20.343 15.660 ;
			LAYER M4 ;
			RECT 0.120 16.044 25.625 16.164 ;
			LAYER M4 ;
			RECT 0.120 16.296 25.625 16.416 ;
			LAYER M4 ;
			RECT 0.120 17.556 20.343 17.676 ;
			LAYER M4 ;
			RECT 0.120 18.060 25.625 18.180 ;
			LAYER M4 ;
			RECT 0.120 18.312 25.625 18.432 ;
			LAYER M4 ;
			RECT 0.120 19.572 20.343 19.692 ;
			LAYER M4 ;
			RECT 0.120 20.076 25.625 20.196 ;
			LAYER M4 ;
			RECT 0.120 20.328 25.625 20.448 ;
			LAYER M4 ;
			RECT 0.120 21.588 20.343 21.708 ;
			LAYER M4 ;
			RECT 0.120 22.092 25.625 22.212 ;
			LAYER M4 ;
			RECT 0.120 22.344 25.625 22.464 ;
			LAYER M4 ;
			RECT 0.120 23.604 20.343 23.724 ;
			LAYER M4 ;
			RECT 0.120 24.108 25.625 24.228 ;
			LAYER M4 ;
			RECT 0.120 24.360 25.625 24.480 ;
			LAYER M4 ;
			RECT 0.120 25.620 20.343 25.740 ;
			LAYER M4 ;
			RECT 0.120 26.124 25.625 26.244 ;
			LAYER M4 ;
			RECT 0.120 26.376 25.625 26.496 ;
			LAYER M4 ;
			RECT 0.120 27.636 20.343 27.756 ;
			LAYER M4 ;
			RECT 0.120 28.140 25.625 28.260 ;
			LAYER M4 ;
			RECT 0.120 28.392 25.625 28.512 ;
			LAYER M4 ;
			RECT 0.120 29.652 20.343 29.772 ;
			LAYER M4 ;
			RECT 0.120 30.156 25.625 30.276 ;
			LAYER M4 ;
			RECT 0.120 30.408 25.625 30.528 ;
			LAYER M4 ;
			RECT 0.120 31.668 20.343 31.788 ;
			LAYER M4 ;
			RECT 0.120 32.172 25.625 32.292 ;
			LAYER M4 ;
			RECT 0.120 32.424 25.625 32.544 ;
			LAYER M4 ;
			RECT 0.120 33.684 20.343 33.804 ;
			LAYER M4 ;
			RECT 0.120 34.188 25.625 34.308 ;
			LAYER M4 ;
			RECT 0.120 34.440 25.625 34.560 ;
			LAYER M4 ;
			RECT 0.120 35.700 20.343 35.820 ;
			LAYER M4 ;
			RECT 0.120 36.204 25.625 36.324 ;
			LAYER M4 ;
			RECT 0.120 36.456 25.625 36.576 ;
			LAYER M4 ;
			RECT 0.120 37.716 20.343 37.836 ;
			LAYER M4 ;
			RECT 0.120 38.220 25.625 38.340 ;
			LAYER M4 ;
			RECT 0.120 38.472 25.625 38.592 ;
			LAYER M4 ;
			RECT 0.120 39.732 20.343 39.852 ;
			LAYER M4 ;
			RECT 0.120 40.236 25.625 40.356 ;
			LAYER M4 ;
			RECT 0.120 40.488 25.625 40.608 ;
			LAYER M4 ;
			RECT 0.120 41.748 20.343 41.868 ;
			LAYER M4 ;
			RECT 0.120 42.252 25.625 42.372 ;
			LAYER M4 ;
			RECT 0.120 42.504 25.625 42.624 ;
			LAYER M4 ;
			RECT 0.120 43.764 20.343 43.884 ;
			LAYER M4 ;
			RECT 0.120 44.268 25.625 44.388 ;
			LAYER M4 ;
			RECT 0.120 44.520 25.625 44.640 ;
			LAYER M4 ;
			RECT 0.120 45.780 20.343 45.900 ;
			LAYER M4 ;
			RECT 0.120 46.284 25.625 46.404 ;
			LAYER M4 ;
			RECT 0.120 46.536 25.625 46.656 ;
			LAYER M4 ;
			RECT 0.120 47.796 20.343 47.916 ;
			LAYER M4 ;
			RECT 0.120 48.300 25.625 48.420 ;
			LAYER M4 ;
			RECT 0.120 48.552 25.625 48.672 ;
			LAYER M4 ;
			RECT 0.120 49.812 20.343 49.932 ;
			LAYER M4 ;
			RECT 0.120 50.316 25.625 50.436 ;
			LAYER M4 ;
			RECT 0.120 50.568 25.625 50.688 ;
			LAYER M4 ;
			RECT 0.120 51.828 20.343 51.948 ;
			LAYER M4 ;
			RECT 0.120 52.332 25.625 52.452 ;
			LAYER M4 ;
			RECT 0.120 52.584 25.625 52.704 ;
			LAYER M4 ;
			RECT 0.120 53.844 20.343 53.964 ;
			LAYER M4 ;
			RECT 0.120 54.348 25.625 54.468 ;
			LAYER M4 ;
			RECT 0.120 54.600 25.625 54.720 ;
			LAYER M4 ;
			RECT 0.120 55.860 20.343 55.980 ;
			LAYER M4 ;
			RECT 0.120 56.364 25.625 56.484 ;
			LAYER M4 ;
			RECT 0.120 56.616 25.625 56.736 ;
			LAYER M4 ;
			RECT 0.120 57.876 20.343 57.996 ;
			LAYER M4 ;
			RECT 0.120 58.380 25.625 58.500 ;
			LAYER M4 ;
			RECT 0.120 58.632 25.625 58.752 ;
			LAYER M4 ;
			RECT 0.120 59.892 20.343 60.012 ;
			LAYER M4 ;
			RECT 0.120 60.396 25.625 60.516 ;
			LAYER M4 ;
			RECT 0.120 60.648 25.625 60.768 ;
			LAYER M4 ;
			RECT 0.120 61.908 20.343 62.028 ;
			LAYER M4 ;
			RECT 0.120 62.412 25.625 62.532 ;
			LAYER M4 ;
			RECT 0.120 62.664 25.625 62.784 ;
			LAYER M4 ;
			RECT 0.120 63.924 20.343 64.044 ;
			LAYER M4 ;
			RECT 0.120 64.428 25.625 64.548 ;
			LAYER M4 ;
			RECT 0.120 64.680 25.625 64.800 ;
			LAYER M4 ;
			RECT 0.120 65.956 25.625 66.076 ;
			LAYER M4 ;
			RECT 0.120 66.580 20.343 66.700 ;
			LAYER M4 ;
			RECT 0.120 66.986 25.625 67.106 ;
			LAYER M4 ;
			RECT 0.120 67.446 25.625 67.566 ;
			LAYER M4 ;
			RECT 0.120 67.906 20.343 68.026 ;
			LAYER M4 ;
			RECT 0.120 68.366 25.625 68.486 ;
			LAYER M4 ;
			RECT 0.120 68.596 25.625 68.716 ;
			LAYER M4 ;
			RECT 0.120 68.988 25.625 69.108 ;
			LAYER M4 ;
			RECT 0.120 70.138 20.343 70.258 ;
			LAYER M4 ;
			RECT 0.120 70.820 25.625 70.940 ;
			LAYER M4 ;
			RECT 0.120 71.732 20.343 71.852 ;
			LAYER M4 ;
			RECT 0.120 72.911 25.625 73.031 ;
			LAYER M4 ;
			RECT 0.120 73.600 25.625 73.720 ;
			LAYER M4 ;
			RECT 0.120 74.060 25.625 74.180 ;
			LAYER M4 ;
			RECT 0.120 74.936 20.343 75.056 ;
			LAYER M4 ;
			RECT 0.120 75.396 25.625 75.516 ;
			LAYER M4 ;
			RECT 0.120 76.264 25.625 76.384 ;
			LAYER M4 ;
			RECT 0.120 76.698 25.625 76.818 ;
			LAYER M4 ;
			RECT 0.120 77.158 20.343 77.278 ;
			LAYER M4 ;
			RECT 0.120 77.568 25.625 77.688 ;
			LAYER M4 ;
			RECT 0.120 78.028 25.625 78.148 ;
			LAYER M4 ;
			RECT 0.120 78.804 20.343 78.924 ;
			LAYER M4 ;
			RECT 0.120 79.308 25.625 79.428 ;
			LAYER M4 ;
			RECT 0.120 79.560 25.625 79.680 ;
			LAYER M4 ;
			RECT 0.120 80.820 20.343 80.940 ;
			LAYER M4 ;
			RECT 0.120 81.324 25.625 81.444 ;
			LAYER M4 ;
			RECT 0.120 81.576 25.625 81.696 ;
			LAYER M4 ;
			RECT 0.120 82.836 20.343 82.956 ;
			LAYER M4 ;
			RECT 0.120 83.340 25.625 83.460 ;
			LAYER M4 ;
			RECT 0.120 83.592 25.625 83.712 ;
			LAYER M4 ;
			RECT 0.120 84.852 20.343 84.972 ;
			LAYER M4 ;
			RECT 0.120 85.356 25.625 85.476 ;
			LAYER M4 ;
			RECT 0.120 85.608 25.625 85.728 ;
			LAYER M4 ;
			RECT 0.120 86.868 20.343 86.988 ;
			LAYER M4 ;
			RECT 0.120 87.372 25.625 87.492 ;
			LAYER M4 ;
			RECT 0.120 87.624 25.625 87.744 ;
			LAYER M4 ;
			RECT 0.120 88.884 20.343 89.004 ;
			LAYER M4 ;
			RECT 0.120 89.388 25.625 89.508 ;
			LAYER M4 ;
			RECT 0.120 89.640 25.625 89.760 ;
			LAYER M4 ;
			RECT 0.120 90.900 20.343 91.020 ;
			LAYER M4 ;
			RECT 0.120 91.404 25.625 91.524 ;
			LAYER M4 ;
			RECT 0.120 91.656 25.625 91.776 ;
			LAYER M4 ;
			RECT 0.120 92.916 20.343 93.036 ;
			LAYER M4 ;
			RECT 0.120 93.420 25.625 93.540 ;
			LAYER M4 ;
			RECT 0.120 93.672 25.625 93.792 ;
			LAYER M4 ;
			RECT 0.120 94.932 20.343 95.052 ;
			LAYER M4 ;
			RECT 0.120 95.436 25.625 95.556 ;
			LAYER M4 ;
			RECT 0.120 95.688 25.625 95.808 ;
			LAYER M4 ;
			RECT 0.120 96.948 20.343 97.068 ;
			LAYER M4 ;
			RECT 0.120 97.452 25.625 97.572 ;
			LAYER M4 ;
			RECT 0.120 97.704 25.625 97.824 ;
			LAYER M4 ;
			RECT 0.120 98.964 20.343 99.084 ;
			LAYER M4 ;
			RECT 0.120 99.468 25.625 99.588 ;
			LAYER M4 ;
			RECT 0.120 99.720 25.625 99.840 ;
			LAYER M4 ;
			RECT 0.120 100.980 20.343 101.100 ;
			LAYER M4 ;
			RECT 0.120 101.484 25.625 101.604 ;
			LAYER M4 ;
			RECT 0.120 101.736 25.625 101.856 ;
			LAYER M4 ;
			RECT 0.120 102.996 20.343 103.116 ;
			LAYER M4 ;
			RECT 0.120 103.500 25.625 103.620 ;
			LAYER M4 ;
			RECT 0.120 103.752 25.625 103.872 ;
			LAYER M4 ;
			RECT 0.120 105.012 20.343 105.132 ;
			LAYER M4 ;
			RECT 0.120 105.516 25.625 105.636 ;
			LAYER M4 ;
			RECT 0.120 105.768 25.625 105.888 ;
			LAYER M4 ;
			RECT 0.120 107.028 20.343 107.148 ;
			LAYER M4 ;
			RECT 0.120 107.532 25.625 107.652 ;
			LAYER M4 ;
			RECT 0.120 107.784 25.625 107.904 ;
			LAYER M4 ;
			RECT 0.120 109.044 20.343 109.164 ;
			LAYER M4 ;
			RECT 0.120 109.548 25.625 109.668 ;
			LAYER M4 ;
			RECT 0.120 109.800 25.625 109.920 ;
			LAYER M4 ;
			RECT 0.120 111.060 20.343 111.180 ;
			LAYER M4 ;
			RECT 0.120 111.564 25.625 111.684 ;
			LAYER M4 ;
			RECT 0.120 111.816 25.625 111.936 ;
			LAYER M4 ;
			RECT 0.120 113.076 20.343 113.196 ;
			LAYER M4 ;
			RECT 0.120 113.580 25.625 113.700 ;
			LAYER M4 ;
			RECT 0.120 113.832 25.625 113.952 ;
			LAYER M4 ;
			RECT 0.120 115.092 20.343 115.212 ;
			LAYER M4 ;
			RECT 0.120 115.596 25.625 115.716 ;
			LAYER M4 ;
			RECT 0.120 115.848 25.625 115.968 ;
			LAYER M4 ;
			RECT 0.120 117.108 20.343 117.228 ;
			LAYER M4 ;
			RECT 0.120 117.612 25.625 117.732 ;
			LAYER M4 ;
			RECT 0.120 117.864 25.625 117.984 ;
			LAYER M4 ;
			RECT 0.120 119.124 20.343 119.244 ;
			LAYER M4 ;
			RECT 0.120 119.628 25.625 119.748 ;
			LAYER M4 ;
			RECT 0.120 119.880 25.625 120.000 ;
			LAYER M4 ;
			RECT 0.120 121.140 20.343 121.260 ;
			LAYER M4 ;
			RECT 0.120 121.644 25.625 121.764 ;
			LAYER M4 ;
			RECT 0.120 121.896 25.625 122.016 ;
			LAYER M4 ;
			RECT 0.120 123.156 20.343 123.276 ;
			LAYER M4 ;
			RECT 0.120 123.660 25.625 123.780 ;
			LAYER M4 ;
			RECT 0.120 123.912 25.625 124.032 ;
			LAYER M4 ;
			RECT 0.120 125.172 20.343 125.292 ;
			LAYER M4 ;
			RECT 0.120 125.676 25.625 125.796 ;
			LAYER M4 ;
			RECT 0.120 125.928 25.625 126.048 ;
			LAYER M4 ;
			RECT 0.120 127.188 20.343 127.308 ;
			LAYER M4 ;
			RECT 0.120 127.692 25.625 127.812 ;
			LAYER M4 ;
			RECT 0.120 127.944 25.625 128.064 ;
			LAYER M4 ;
			RECT 0.120 129.204 20.343 129.324 ;
			LAYER M4 ;
			RECT 0.120 129.708 25.625 129.828 ;
			LAYER M4 ;
			RECT 0.120 129.960 25.625 130.080 ;
			LAYER M4 ;
			RECT 0.120 131.220 20.343 131.340 ;
			LAYER M4 ;
			RECT 0.120 131.724 25.625 131.844 ;
			LAYER M4 ;
			RECT 0.120 131.976 25.625 132.096 ;
			LAYER M4 ;
			RECT 0.120 133.236 20.343 133.356 ;
			LAYER M4 ;
			RECT 0.120 133.740 25.625 133.860 ;
			LAYER M4 ;
			RECT 0.120 133.992 25.625 134.112 ;
			LAYER M4 ;
			RECT 0.120 135.252 20.343 135.372 ;
			LAYER M4 ;
			RECT 0.120 135.756 25.625 135.876 ;
			LAYER M4 ;
			RECT 0.120 136.008 25.625 136.128 ;
			LAYER M4 ;
			RECT 0.120 137.268 20.343 137.388 ;
			LAYER M4 ;
			RECT 0.120 137.772 25.625 137.892 ;
			LAYER M4 ;
			RECT 0.120 138.024 25.625 138.144 ;
			LAYER M4 ;
			RECT 0.120 139.284 20.343 139.404 ;
			LAYER M4 ;
			RECT 0.120 139.788 25.625 139.908 ;
			LAYER M4 ;
			RECT 0.120 140.040 25.625 140.160 ;
			LAYER M4 ;
			RECT 0.120 141.300 20.343 141.420 ;
			LAYER M4 ;
			RECT 0.120 141.804 25.625 141.924 ;
			LAYER M4 ;
			RECT 0.120 142.056 25.625 142.176 ;
		END
	END VDDM

	PIN VSS
		DIRECTION INOUT ;
		USE GROUND ;
		PORT
			LAYER M4 ;
			RECT 0.120 1.176 25.625 1.296 ;
			LAYER M4 ;
			RECT 0.120 1.680 25.625 1.800 ;
			LAYER M4 ;
			RECT 0.120 2.688 25.625 2.808 ;
			LAYER M4 ;
			RECT 0.120 3.192 25.625 3.312 ;
			LAYER M4 ;
			RECT 0.120 3.696 25.625 3.816 ;
			LAYER M4 ;
			RECT 0.120 4.704 25.625 4.824 ;
			LAYER M4 ;
			RECT 0.120 5.208 25.625 5.328 ;
			LAYER M4 ;
			RECT 0.120 5.712 25.625 5.832 ;
			LAYER M4 ;
			RECT 0.120 6.720 25.625 6.840 ;
			LAYER M4 ;
			RECT 0.120 7.224 25.625 7.344 ;
			LAYER M4 ;
			RECT 0.120 7.728 25.625 7.848 ;
			LAYER M4 ;
			RECT 0.120 8.736 25.625 8.856 ;
			LAYER M4 ;
			RECT 0.120 9.240 25.625 9.360 ;
			LAYER M4 ;
			RECT 0.120 9.744 25.625 9.864 ;
			LAYER M4 ;
			RECT 0.120 10.752 25.625 10.872 ;
			LAYER M4 ;
			RECT 0.120 11.256 25.625 11.376 ;
			LAYER M4 ;
			RECT 0.120 11.760 25.625 11.880 ;
			LAYER M4 ;
			RECT 0.120 12.768 25.625 12.888 ;
			LAYER M4 ;
			RECT 0.120 13.272 25.625 13.392 ;
			LAYER M4 ;
			RECT 0.120 13.776 25.625 13.896 ;
			LAYER M4 ;
			RECT 0.120 14.784 25.625 14.904 ;
			LAYER M4 ;
			RECT 0.120 15.288 25.625 15.408 ;
			LAYER M4 ;
			RECT 0.120 15.792 25.625 15.912 ;
			LAYER M4 ;
			RECT 0.120 16.800 25.625 16.920 ;
			LAYER M4 ;
			RECT 0.120 17.304 25.625 17.424 ;
			LAYER M4 ;
			RECT 0.120 17.808 25.625 17.928 ;
			LAYER M4 ;
			RECT 0.120 18.816 25.625 18.936 ;
			LAYER M4 ;
			RECT 0.120 19.320 25.625 19.440 ;
			LAYER M4 ;
			RECT 0.120 19.824 25.625 19.944 ;
			LAYER M4 ;
			RECT 0.120 20.832 25.625 20.952 ;
			LAYER M4 ;
			RECT 0.120 21.336 25.625 21.456 ;
			LAYER M4 ;
			RECT 0.120 21.840 25.625 21.960 ;
			LAYER M4 ;
			RECT 0.120 22.848 25.625 22.968 ;
			LAYER M4 ;
			RECT 0.120 23.352 25.625 23.472 ;
			LAYER M4 ;
			RECT 0.120 23.856 25.625 23.976 ;
			LAYER M4 ;
			RECT 0.120 24.864 25.625 24.984 ;
			LAYER M4 ;
			RECT 0.120 25.368 25.625 25.488 ;
			LAYER M4 ;
			RECT 0.120 25.872 25.625 25.992 ;
			LAYER M4 ;
			RECT 0.120 26.880 25.625 27.000 ;
			LAYER M4 ;
			RECT 0.120 27.384 25.625 27.504 ;
			LAYER M4 ;
			RECT 0.120 27.888 25.625 28.008 ;
			LAYER M4 ;
			RECT 0.120 28.896 25.625 29.016 ;
			LAYER M4 ;
			RECT 0.120 29.400 25.625 29.520 ;
			LAYER M4 ;
			RECT 0.120 29.904 25.625 30.024 ;
			LAYER M4 ;
			RECT 0.120 30.912 25.625 31.032 ;
			LAYER M4 ;
			RECT 0.120 31.416 25.625 31.536 ;
			LAYER M4 ;
			RECT 0.120 31.920 25.625 32.040 ;
			LAYER M4 ;
			RECT 0.120 32.928 25.625 33.048 ;
			LAYER M4 ;
			RECT 0.120 33.432 25.625 33.552 ;
			LAYER M4 ;
			RECT 0.120 33.936 25.625 34.056 ;
			LAYER M4 ;
			RECT 0.120 34.944 25.625 35.064 ;
			LAYER M4 ;
			RECT 0.120 35.448 25.625 35.568 ;
			LAYER M4 ;
			RECT 0.120 35.952 25.625 36.072 ;
			LAYER M4 ;
			RECT 0.120 36.960 25.625 37.080 ;
			LAYER M4 ;
			RECT 0.120 37.464 25.625 37.584 ;
			LAYER M4 ;
			RECT 0.120 37.968 25.625 38.088 ;
			LAYER M4 ;
			RECT 0.120 38.976 25.625 39.096 ;
			LAYER M4 ;
			RECT 0.120 39.480 25.625 39.600 ;
			LAYER M4 ;
			RECT 0.120 39.984 25.625 40.104 ;
			LAYER M4 ;
			RECT 0.120 40.992 25.625 41.112 ;
			LAYER M4 ;
			RECT 0.120 41.496 25.625 41.616 ;
			LAYER M4 ;
			RECT 0.120 42.000 25.625 42.120 ;
			LAYER M4 ;
			RECT 0.120 43.008 25.625 43.128 ;
			LAYER M4 ;
			RECT 0.120 43.512 25.625 43.632 ;
			LAYER M4 ;
			RECT 0.120 44.016 25.625 44.136 ;
			LAYER M4 ;
			RECT 0.120 45.024 25.625 45.144 ;
			LAYER M4 ;
			RECT 0.120 45.528 25.625 45.648 ;
			LAYER M4 ;
			RECT 0.120 46.032 25.625 46.152 ;
			LAYER M4 ;
			RECT 0.120 47.040 25.625 47.160 ;
			LAYER M4 ;
			RECT 0.120 47.544 25.625 47.664 ;
			LAYER M4 ;
			RECT 0.120 48.048 25.625 48.168 ;
			LAYER M4 ;
			RECT 0.120 49.056 25.625 49.176 ;
			LAYER M4 ;
			RECT 0.120 49.560 25.625 49.680 ;
			LAYER M4 ;
			RECT 0.120 50.064 25.625 50.184 ;
			LAYER M4 ;
			RECT 0.120 51.072 25.625 51.192 ;
			LAYER M4 ;
			RECT 0.120 51.576 25.625 51.696 ;
			LAYER M4 ;
			RECT 0.120 52.080 25.625 52.200 ;
			LAYER M4 ;
			RECT 0.120 53.088 25.625 53.208 ;
			LAYER M4 ;
			RECT 0.120 53.592 25.625 53.712 ;
			LAYER M4 ;
			RECT 0.120 54.096 25.625 54.216 ;
			LAYER M4 ;
			RECT 0.120 55.104 25.625 55.224 ;
			LAYER M4 ;
			RECT 0.120 55.608 25.625 55.728 ;
			LAYER M4 ;
			RECT 0.120 56.112 25.625 56.232 ;
			LAYER M4 ;
			RECT 0.120 57.120 25.625 57.240 ;
			LAYER M4 ;
			RECT 0.120 57.624 25.625 57.744 ;
			LAYER M4 ;
			RECT 0.120 58.128 25.625 58.248 ;
			LAYER M4 ;
			RECT 0.120 59.136 25.625 59.256 ;
			LAYER M4 ;
			RECT 0.120 59.640 25.625 59.760 ;
			LAYER M4 ;
			RECT 0.120 60.144 25.625 60.264 ;
			LAYER M4 ;
			RECT 0.120 61.152 25.625 61.272 ;
			LAYER M4 ;
			RECT 0.120 61.656 25.625 61.776 ;
			LAYER M4 ;
			RECT 0.120 62.160 25.625 62.280 ;
			LAYER M4 ;
			RECT 0.120 63.168 25.625 63.288 ;
			LAYER M4 ;
			RECT 0.120 63.672 25.625 63.792 ;
			LAYER M4 ;
			RECT 0.120 64.176 25.625 64.296 ;
			LAYER M4 ;
			RECT 0.120 65.184 25.625 65.304 ;
			LAYER M4 ;
			RECT 0.120 66.350 25.625 66.470 ;
			LAYER M4 ;
			RECT 0.120 67.216 25.625 67.336 ;
			LAYER M4 ;
			RECT 0.120 67.676 25.625 67.796 ;
			LAYER M4 ;
			RECT 0.120 68.136 25.625 68.256 ;
			LAYER M4 ;
			RECT 0.120 69.218 25.625 69.338 ;
			LAYER M4 ;
			RECT 0.120 69.908 25.625 70.028 ;
			LAYER M4 ;
			RECT 0.120 71.050 25.625 71.170 ;
			LAYER M4 ;
			RECT 0.120 71.962 25.625 72.082 ;
			LAYER M4 ;
			RECT 0.120 72.681 25.625 72.801 ;
			LAYER M4 ;
			RECT 0.120 73.830 25.625 73.950 ;
			LAYER M4 ;
			RECT 0.120 74.290 25.625 74.410 ;
			LAYER M4 ;
			RECT 0.120 74.706 25.625 74.826 ;
			LAYER M4 ;
			RECT 0.120 75.166 25.625 75.286 ;
			LAYER M4 ;
			RECT 0.120 75.626 25.625 75.746 ;
			LAYER M4 ;
			RECT 0.120 76.034 25.625 76.154 ;
			LAYER M4 ;
			RECT 0.120 76.928 25.625 77.048 ;
			LAYER M4 ;
			RECT 0.120 77.798 25.625 77.918 ;
			LAYER M4 ;
			RECT 0.120 78.552 25.625 78.672 ;
			LAYER M4 ;
			RECT 0.120 79.056 25.625 79.176 ;
			LAYER M4 ;
			RECT 0.120 80.064 25.625 80.184 ;
			LAYER M4 ;
			RECT 0.120 80.568 25.625 80.688 ;
			LAYER M4 ;
			RECT 0.120 81.072 25.625 81.192 ;
			LAYER M4 ;
			RECT 0.120 82.080 25.625 82.200 ;
			LAYER M4 ;
			RECT 0.120 82.584 25.625 82.704 ;
			LAYER M4 ;
			RECT 0.120 83.088 25.625 83.208 ;
			LAYER M4 ;
			RECT 0.120 84.096 25.625 84.216 ;
			LAYER M4 ;
			RECT 0.120 84.600 25.625 84.720 ;
			LAYER M4 ;
			RECT 0.120 85.104 25.625 85.224 ;
			LAYER M4 ;
			RECT 0.120 86.112 25.625 86.232 ;
			LAYER M4 ;
			RECT 0.120 86.616 25.625 86.736 ;
			LAYER M4 ;
			RECT 0.120 87.120 25.625 87.240 ;
			LAYER M4 ;
			RECT 0.120 88.128 25.625 88.248 ;
			LAYER M4 ;
			RECT 0.120 88.632 25.625 88.752 ;
			LAYER M4 ;
			RECT 0.120 89.136 25.625 89.256 ;
			LAYER M4 ;
			RECT 0.120 90.144 25.625 90.264 ;
			LAYER M4 ;
			RECT 0.120 90.648 25.625 90.768 ;
			LAYER M4 ;
			RECT 0.120 91.152 25.625 91.272 ;
			LAYER M4 ;
			RECT 0.120 92.160 25.625 92.280 ;
			LAYER M4 ;
			RECT 0.120 92.664 25.625 92.784 ;
			LAYER M4 ;
			RECT 0.120 93.168 25.625 93.288 ;
			LAYER M4 ;
			RECT 0.120 94.176 25.625 94.296 ;
			LAYER M4 ;
			RECT 0.120 94.680 25.625 94.800 ;
			LAYER M4 ;
			RECT 0.120 95.184 25.625 95.304 ;
			LAYER M4 ;
			RECT 0.120 96.192 25.625 96.312 ;
			LAYER M4 ;
			RECT 0.120 96.696 25.625 96.816 ;
			LAYER M4 ;
			RECT 0.120 97.200 25.625 97.320 ;
			LAYER M4 ;
			RECT 0.120 98.208 25.625 98.328 ;
			LAYER M4 ;
			RECT 0.120 98.712 25.625 98.832 ;
			LAYER M4 ;
			RECT 0.120 99.216 25.625 99.336 ;
			LAYER M4 ;
			RECT 0.120 100.224 25.625 100.344 ;
			LAYER M4 ;
			RECT 0.120 100.728 25.625 100.848 ;
			LAYER M4 ;
			RECT 0.120 101.232 25.625 101.352 ;
			LAYER M4 ;
			RECT 0.120 102.240 25.625 102.360 ;
			LAYER M4 ;
			RECT 0.120 102.744 25.625 102.864 ;
			LAYER M4 ;
			RECT 0.120 103.248 25.625 103.368 ;
			LAYER M4 ;
			RECT 0.120 104.256 25.625 104.376 ;
			LAYER M4 ;
			RECT 0.120 104.760 25.625 104.880 ;
			LAYER M4 ;
			RECT 0.120 105.264 25.625 105.384 ;
			LAYER M4 ;
			RECT 0.120 106.272 25.625 106.392 ;
			LAYER M4 ;
			RECT 0.120 106.776 25.625 106.896 ;
			LAYER M4 ;
			RECT 0.120 107.280 25.625 107.400 ;
			LAYER M4 ;
			RECT 0.120 108.288 25.625 108.408 ;
			LAYER M4 ;
			RECT 0.120 108.792 25.625 108.912 ;
			LAYER M4 ;
			RECT 0.120 109.296 25.625 109.416 ;
			LAYER M4 ;
			RECT 0.120 110.304 25.625 110.424 ;
			LAYER M4 ;
			RECT 0.120 110.808 25.625 110.928 ;
			LAYER M4 ;
			RECT 0.120 111.312 25.625 111.432 ;
			LAYER M4 ;
			RECT 0.120 112.320 25.625 112.440 ;
			LAYER M4 ;
			RECT 0.120 112.824 25.625 112.944 ;
			LAYER M4 ;
			RECT 0.120 113.328 25.625 113.448 ;
			LAYER M4 ;
			RECT 0.120 114.336 25.625 114.456 ;
			LAYER M4 ;
			RECT 0.120 114.840 25.625 114.960 ;
			LAYER M4 ;
			RECT 0.120 115.344 25.625 115.464 ;
			LAYER M4 ;
			RECT 0.120 116.352 25.625 116.472 ;
			LAYER M4 ;
			RECT 0.120 116.856 25.625 116.976 ;
			LAYER M4 ;
			RECT 0.120 117.360 25.625 117.480 ;
			LAYER M4 ;
			RECT 0.120 118.368 25.625 118.488 ;
			LAYER M4 ;
			RECT 0.120 118.872 25.625 118.992 ;
			LAYER M4 ;
			RECT 0.120 119.376 25.625 119.496 ;
			LAYER M4 ;
			RECT 0.120 120.384 25.625 120.504 ;
			LAYER M4 ;
			RECT 0.120 120.888 25.625 121.008 ;
			LAYER M4 ;
			RECT 0.120 121.392 25.625 121.512 ;
			LAYER M4 ;
			RECT 0.120 122.400 25.625 122.520 ;
			LAYER M4 ;
			RECT 0.120 122.904 25.625 123.024 ;
			LAYER M4 ;
			RECT 0.120 123.408 25.625 123.528 ;
			LAYER M4 ;
			RECT 0.120 124.416 25.625 124.536 ;
			LAYER M4 ;
			RECT 0.120 124.920 25.625 125.040 ;
			LAYER M4 ;
			RECT 0.120 125.424 25.625 125.544 ;
			LAYER M4 ;
			RECT 0.120 126.432 25.625 126.552 ;
			LAYER M4 ;
			RECT 0.120 126.936 25.625 127.056 ;
			LAYER M4 ;
			RECT 0.120 127.440 25.625 127.560 ;
			LAYER M4 ;
			RECT 0.120 128.448 25.625 128.568 ;
			LAYER M4 ;
			RECT 0.120 128.952 25.625 129.072 ;
			LAYER M4 ;
			RECT 0.120 129.456 25.625 129.576 ;
			LAYER M4 ;
			RECT 0.120 130.464 25.625 130.584 ;
			LAYER M4 ;
			RECT 0.120 130.968 25.625 131.088 ;
			LAYER M4 ;
			RECT 0.120 131.472 25.625 131.592 ;
			LAYER M4 ;
			RECT 0.120 132.480 25.625 132.600 ;
			LAYER M4 ;
			RECT 0.120 132.984 25.625 133.104 ;
			LAYER M4 ;
			RECT 0.120 133.488 25.625 133.608 ;
			LAYER M4 ;
			RECT 0.120 134.496 25.625 134.616 ;
			LAYER M4 ;
			RECT 0.120 135.000 25.625 135.120 ;
			LAYER M4 ;
			RECT 0.120 135.504 25.625 135.624 ;
			LAYER M4 ;
			RECT 0.120 136.512 25.625 136.632 ;
			LAYER M4 ;
			RECT 0.120 137.016 25.625 137.136 ;
			LAYER M4 ;
			RECT 0.120 137.520 25.625 137.640 ;
			LAYER M4 ;
			RECT 0.120 138.528 25.625 138.648 ;
			LAYER M4 ;
			RECT 0.120 139.032 25.625 139.152 ;
			LAYER M4 ;
			RECT 0.120 139.536 25.625 139.656 ;
			LAYER M4 ;
			RECT 0.120 140.544 25.625 140.664 ;
			LAYER M4 ;
			RECT 0.120 141.048 25.625 141.168 ;
			LAYER M4 ;
			RECT 0.120 141.552 25.625 141.672 ;
			LAYER M4 ;
			RECT 0.120 142.560 25.625 142.680 ;
		END
	END VSS

	PIN WEB
		DIRECTION INPUT ;
		USE SIGNAL ;
		PORT
			LAYER M1 ;
			RECT 25.497 70.088 25.745 70.168 ;
			LAYER M2 ;
			RECT 25.497 70.088 25.745 70.168 ;
			LAYER M3 ;
			RECT 25.497 70.088 25.745 70.168 ;
		END
	END WEB

	PIN WTSEL[0]
		DIRECTION INPUT ;
		USE SIGNAL ;
		PORT
			LAYER M1 ;
			RECT 25.497 69.896 25.745 69.976 ;
			LAYER M2 ;
			RECT 25.497 69.896 25.745 69.976 ;
			LAYER M3 ;
			RECT 25.497 69.896 25.745 69.976 ;
		END
	END WTSEL[0]

	PIN WTSEL[1]
		DIRECTION INPUT ;
		USE SIGNAL ;
		PORT
			LAYER M1 ;
			RECT 25.497 71.048 25.745 71.128 ;
			LAYER M2 ;
			RECT 25.497 71.048 25.745 71.128 ;
			LAYER M3 ;
			RECT 25.497 71.048 25.745 71.128 ;
		END
	END WTSEL[1]

	OBS
		LAYER M1 ;
		RECT 0.000 0.000 25.745 143.856 ;
		LAYER M2 ;
		RECT 0.000 0.000 25.745 143.856 ;
		LAYER M3 ;
		RECT 0.000 0.000 25.745 143.856 ;
		LAYER M4 ;
		RECT 0.283 143.305 25.345 143.425 ;
		LAYER M4 ;
		RECT 0.300 0.431 25.345 0.551 ;
		LAYER M4 ;
		RECT 0.723 77.368 20.793 77.445 ;
		LAYER M4 ;
		RECT 1.218 70.325 20.793 70.423 ;
		LAYER M4 ;
		RECT 1.218 70.505 20.793 70.603 ;
		LAYER M4 ;
		RECT 1.218 70.685 20.793 70.783 ;
		LAYER M4 ;
		RECT 1.218 71.237 20.793 71.335 ;
		LAYER M4 ;
		RECT 1.218 71.417 20.793 71.515 ;
		LAYER M4 ;
		RECT 1.218 71.597 20.793 71.695 ;
		LAYER M4 ;
		RECT 1.218 72.183 20.793 72.281 ;
		LAYER M4 ;
		RECT 1.218 72.363 20.793 72.461 ;
		LAYER M4 ;
		RECT 1.218 72.543 20.793 72.641 ;
		LAYER M4 ;
		RECT 1.218 73.095 20.793 73.193 ;
		LAYER M4 ;
		RECT 1.218 73.275 20.793 73.373 ;
		LAYER M4 ;
		RECT 1.218 73.455 20.793 73.553 ;
		LAYER M4 ;
		RECT 1.668 69.373 20.793 69.471 ;
		LAYER M4 ;
		RECT 1.668 69.553 20.793 69.651 ;
		LAYER M4 ;
		RECT 1.668 69.733 20.793 69.831 ;
		LAYER M4 ;
		RECT 12.787 1.330 13.789 1.394 ;
		LAYER M4 ;
		RECT 12.787 2.590 13.789 2.654 ;
		LAYER M4 ;
		RECT 12.787 3.346 13.789 3.410 ;
		LAYER M4 ;
		RECT 12.787 4.606 13.789 4.670 ;
		LAYER M4 ;
		RECT 12.787 5.362 13.789 5.426 ;
		LAYER M4 ;
		RECT 12.787 6.622 13.789 6.686 ;
		LAYER M4 ;
		RECT 12.787 7.378 13.789 7.442 ;
		LAYER M4 ;
		RECT 12.787 8.638 13.789 8.702 ;
		LAYER M4 ;
		RECT 12.787 9.394 13.789 9.458 ;
		LAYER M4 ;
		RECT 12.787 10.654 13.789 10.718 ;
		LAYER M4 ;
		RECT 12.787 11.410 13.789 11.474 ;
		LAYER M4 ;
		RECT 12.787 12.670 13.789 12.734 ;
		LAYER M4 ;
		RECT 12.787 13.426 13.789 13.490 ;
		LAYER M4 ;
		RECT 12.787 14.686 13.789 14.750 ;
		LAYER M4 ;
		RECT 12.787 15.442 13.789 15.506 ;
		LAYER M4 ;
		RECT 12.787 16.702 13.789 16.766 ;
		LAYER M4 ;
		RECT 12.787 17.458 13.789 17.522 ;
		LAYER M4 ;
		RECT 12.787 18.718 13.789 18.782 ;
		LAYER M4 ;
		RECT 12.787 19.474 13.789 19.538 ;
		LAYER M4 ;
		RECT 12.787 20.734 13.789 20.798 ;
		LAYER M4 ;
		RECT 12.787 21.490 13.789 21.554 ;
		LAYER M4 ;
		RECT 12.787 22.750 13.789 22.814 ;
		LAYER M4 ;
		RECT 12.787 23.506 13.789 23.570 ;
		LAYER M4 ;
		RECT 12.787 24.766 13.789 24.830 ;
		LAYER M4 ;
		RECT 12.787 25.522 13.789 25.586 ;
		LAYER M4 ;
		RECT 12.787 26.782 13.789 26.846 ;
		LAYER M4 ;
		RECT 12.787 27.538 13.789 27.602 ;
		LAYER M4 ;
		RECT 12.787 28.798 13.789 28.862 ;
		LAYER M4 ;
		RECT 12.787 29.554 13.789 29.618 ;
		LAYER M4 ;
		RECT 12.787 30.814 13.789 30.878 ;
		LAYER M4 ;
		RECT 12.787 31.570 13.789 31.634 ;
		LAYER M4 ;
		RECT 12.787 32.830 13.789 32.894 ;
		LAYER M4 ;
		RECT 12.787 33.586 13.789 33.650 ;
		LAYER M4 ;
		RECT 12.787 34.846 13.789 34.910 ;
		LAYER M4 ;
		RECT 12.787 35.602 13.789 35.666 ;
		LAYER M4 ;
		RECT 12.787 36.862 13.789 36.926 ;
		LAYER M4 ;
		RECT 12.787 37.618 13.789 37.682 ;
		LAYER M4 ;
		RECT 12.787 38.878 13.789 38.942 ;
		LAYER M4 ;
		RECT 12.787 39.634 13.789 39.698 ;
		LAYER M4 ;
		RECT 12.787 40.894 13.789 40.958 ;
		LAYER M4 ;
		RECT 12.787 41.650 13.789 41.714 ;
		LAYER M4 ;
		RECT 12.787 42.910 13.789 42.974 ;
		LAYER M4 ;
		RECT 12.787 43.666 13.789 43.730 ;
		LAYER M4 ;
		RECT 12.787 44.926 13.789 44.990 ;
		LAYER M4 ;
		RECT 12.787 45.682 13.789 45.746 ;
		LAYER M4 ;
		RECT 12.787 46.942 13.789 47.006 ;
		LAYER M4 ;
		RECT 12.787 47.698 13.789 47.762 ;
		LAYER M4 ;
		RECT 12.787 48.958 13.789 49.022 ;
		LAYER M4 ;
		RECT 12.787 49.714 13.789 49.778 ;
		LAYER M4 ;
		RECT 12.787 50.974 13.789 51.038 ;
		LAYER M4 ;
		RECT 12.787 51.730 13.789 51.794 ;
		LAYER M4 ;
		RECT 12.787 52.990 13.789 53.054 ;
		LAYER M4 ;
		RECT 12.787 53.746 13.789 53.810 ;
		LAYER M4 ;
		RECT 12.787 55.006 13.789 55.070 ;
		LAYER M4 ;
		RECT 12.787 55.762 13.789 55.826 ;
		LAYER M4 ;
		RECT 12.787 57.022 13.789 57.086 ;
		LAYER M4 ;
		RECT 12.787 57.778 13.789 57.842 ;
		LAYER M4 ;
		RECT 12.787 59.038 13.789 59.102 ;
		LAYER M4 ;
		RECT 12.787 59.794 13.789 59.858 ;
		LAYER M4 ;
		RECT 12.787 61.054 13.789 61.118 ;
		LAYER M4 ;
		RECT 12.787 61.810 13.789 61.874 ;
		LAYER M4 ;
		RECT 12.787 63.070 13.789 63.134 ;
		LAYER M4 ;
		RECT 12.787 63.826 13.789 63.890 ;
		LAYER M4 ;
		RECT 12.787 65.086 13.789 65.150 ;
		LAYER M4 ;
		RECT 12.787 78.706 13.789 78.770 ;
		LAYER M4 ;
		RECT 12.787 79.966 13.789 80.030 ;
		LAYER M4 ;
		RECT 12.787 80.722 13.789 80.786 ;
		LAYER M4 ;
		RECT 12.787 81.982 13.789 82.046 ;
		LAYER M4 ;
		RECT 12.787 82.738 13.789 82.802 ;
		LAYER M4 ;
		RECT 12.787 83.998 13.789 84.062 ;
		LAYER M4 ;
		RECT 12.787 84.754 13.789 84.818 ;
		LAYER M4 ;
		RECT 12.787 86.014 13.789 86.078 ;
		LAYER M4 ;
		RECT 12.787 86.770 13.789 86.834 ;
		LAYER M4 ;
		RECT 12.787 88.030 13.789 88.094 ;
		LAYER M4 ;
		RECT 12.787 88.786 13.789 88.850 ;
		LAYER M4 ;
		RECT 12.787 90.046 13.789 90.110 ;
		LAYER M4 ;
		RECT 12.787 90.802 13.789 90.866 ;
		LAYER M4 ;
		RECT 12.787 92.062 13.789 92.126 ;
		LAYER M4 ;
		RECT 12.787 92.818 13.789 92.882 ;
		LAYER M4 ;
		RECT 12.787 94.078 13.789 94.142 ;
		LAYER M4 ;
		RECT 12.787 94.834 13.789 94.898 ;
		LAYER M4 ;
		RECT 12.787 96.094 13.789 96.158 ;
		LAYER M4 ;
		RECT 12.787 96.850 13.789 96.914 ;
		LAYER M4 ;
		RECT 12.787 98.110 13.789 98.174 ;
		LAYER M4 ;
		RECT 12.787 98.866 13.789 98.930 ;
		LAYER M4 ;
		RECT 12.787 100.126 13.789 100.190 ;
		LAYER M4 ;
		RECT 12.787 100.882 13.789 100.946 ;
		LAYER M4 ;
		RECT 12.787 102.142 13.789 102.206 ;
		LAYER M4 ;
		RECT 12.787 102.898 13.789 102.962 ;
		LAYER M4 ;
		RECT 12.787 104.158 13.789 104.222 ;
		LAYER M4 ;
		RECT 12.787 104.914 13.789 104.978 ;
		LAYER M4 ;
		RECT 12.787 106.174 13.789 106.238 ;
		LAYER M4 ;
		RECT 12.787 106.930 13.789 106.994 ;
		LAYER M4 ;
		RECT 12.787 108.190 13.789 108.254 ;
		LAYER M4 ;
		RECT 12.787 108.946 13.789 109.010 ;
		LAYER M4 ;
		RECT 12.787 110.206 13.789 110.270 ;
		LAYER M4 ;
		RECT 12.787 110.962 13.789 111.026 ;
		LAYER M4 ;
		RECT 12.787 112.222 13.789 112.286 ;
		LAYER M4 ;
		RECT 12.787 112.978 13.789 113.042 ;
		LAYER M4 ;
		RECT 12.787 114.238 13.789 114.302 ;
		LAYER M4 ;
		RECT 12.787 114.994 13.789 115.058 ;
		LAYER M4 ;
		RECT 12.787 116.254 13.789 116.318 ;
		LAYER M4 ;
		RECT 12.787 117.010 13.789 117.074 ;
		LAYER M4 ;
		RECT 12.787 118.270 13.789 118.334 ;
		LAYER M4 ;
		RECT 12.787 119.026 13.789 119.090 ;
		LAYER M4 ;
		RECT 12.787 120.286 13.789 120.350 ;
		LAYER M4 ;
		RECT 12.787 121.042 13.789 121.106 ;
		LAYER M4 ;
		RECT 12.787 122.302 13.789 122.366 ;
		LAYER M4 ;
		RECT 12.787 123.058 13.789 123.122 ;
		LAYER M4 ;
		RECT 12.787 124.318 13.789 124.382 ;
		LAYER M4 ;
		RECT 12.787 125.074 13.789 125.138 ;
		LAYER M4 ;
		RECT 12.787 126.334 13.789 126.398 ;
		LAYER M4 ;
		RECT 12.787 127.090 13.789 127.154 ;
		LAYER M4 ;
		RECT 12.787 128.350 13.789 128.414 ;
		LAYER M4 ;
		RECT 12.787 129.106 13.789 129.170 ;
		LAYER M4 ;
		RECT 12.787 130.366 13.789 130.430 ;
		LAYER M4 ;
		RECT 12.787 131.122 13.789 131.186 ;
		LAYER M4 ;
		RECT 12.787 132.382 13.789 132.446 ;
		LAYER M4 ;
		RECT 12.787 133.138 13.789 133.202 ;
		LAYER M4 ;
		RECT 12.787 134.398 13.789 134.462 ;
		LAYER M4 ;
		RECT 12.787 135.154 13.789 135.218 ;
		LAYER M4 ;
		RECT 12.787 136.414 13.789 136.478 ;
		LAYER M4 ;
		RECT 12.787 137.170 13.789 137.234 ;
		LAYER M4 ;
		RECT 12.787 138.430 13.789 138.494 ;
		LAYER M4 ;
		RECT 12.787 139.186 13.789 139.250 ;
		LAYER M4 ;
		RECT 12.787 140.446 13.789 140.510 ;
		LAYER M4 ;
		RECT 12.787 141.202 13.789 141.266 ;
		LAYER M4 ;
		RECT 12.787 142.462 13.789 142.526 ;
		LAYER M4 ;
		RECT 14.581 1.337 16.559 1.387 ;
		LAYER M4 ;
		RECT 14.581 2.597 16.559 2.647 ;
		LAYER M4 ;
		RECT 14.581 3.353 16.559 3.403 ;
		LAYER M4 ;
		RECT 14.581 4.613 16.559 4.663 ;
		LAYER M4 ;
		RECT 14.581 5.369 16.559 5.419 ;
		LAYER M4 ;
		RECT 14.581 6.629 16.559 6.679 ;
		LAYER M4 ;
		RECT 14.581 7.385 16.559 7.435 ;
		LAYER M4 ;
		RECT 14.581 8.645 16.559 8.695 ;
		LAYER M4 ;
		RECT 14.581 9.401 16.559 9.451 ;
		LAYER M4 ;
		RECT 14.581 10.661 16.559 10.711 ;
		LAYER M4 ;
		RECT 14.581 11.417 16.559 11.467 ;
		LAYER M4 ;
		RECT 14.581 12.677 16.559 12.727 ;
		LAYER M4 ;
		RECT 14.581 13.433 16.559 13.483 ;
		LAYER M4 ;
		RECT 14.581 14.693 16.559 14.743 ;
		LAYER M4 ;
		RECT 14.581 15.449 16.559 15.499 ;
		LAYER M4 ;
		RECT 14.581 16.709 16.559 16.759 ;
		LAYER M4 ;
		RECT 14.581 17.465 16.559 17.515 ;
		LAYER M4 ;
		RECT 14.581 18.725 16.559 18.775 ;
		LAYER M4 ;
		RECT 14.581 19.481 16.559 19.531 ;
		LAYER M4 ;
		RECT 14.581 20.741 16.559 20.791 ;
		LAYER M4 ;
		RECT 14.581 21.497 16.559 21.547 ;
		LAYER M4 ;
		RECT 14.581 22.757 16.559 22.807 ;
		LAYER M4 ;
		RECT 14.581 23.513 16.559 23.563 ;
		LAYER M4 ;
		RECT 14.581 24.773 16.559 24.823 ;
		LAYER M4 ;
		RECT 14.581 25.529 16.559 25.579 ;
		LAYER M4 ;
		RECT 14.581 26.789 16.559 26.839 ;
		LAYER M4 ;
		RECT 14.581 27.545 16.559 27.595 ;
		LAYER M4 ;
		RECT 14.581 28.805 16.559 28.855 ;
		LAYER M4 ;
		RECT 14.581 29.561 16.559 29.611 ;
		LAYER M4 ;
		RECT 14.581 30.821 16.559 30.871 ;
		LAYER M4 ;
		RECT 14.581 31.577 16.559 31.627 ;
		LAYER M4 ;
		RECT 14.581 32.837 16.559 32.887 ;
		LAYER M4 ;
		RECT 14.581 33.593 16.559 33.643 ;
		LAYER M4 ;
		RECT 14.581 34.853 16.559 34.903 ;
		LAYER M4 ;
		RECT 14.581 35.609 16.559 35.659 ;
		LAYER M4 ;
		RECT 14.581 36.869 16.559 36.919 ;
		LAYER M4 ;
		RECT 14.581 37.625 16.559 37.675 ;
		LAYER M4 ;
		RECT 14.581 38.885 16.559 38.935 ;
		LAYER M4 ;
		RECT 14.581 39.641 16.559 39.691 ;
		LAYER M4 ;
		RECT 14.581 40.901 16.559 40.951 ;
		LAYER M4 ;
		RECT 14.581 41.657 16.559 41.707 ;
		LAYER M4 ;
		RECT 14.581 42.917 16.559 42.967 ;
		LAYER M4 ;
		RECT 14.581 43.673 16.559 43.723 ;
		LAYER M4 ;
		RECT 14.581 44.933 16.559 44.983 ;
		LAYER M4 ;
		RECT 14.581 45.689 16.559 45.739 ;
		LAYER M4 ;
		RECT 14.581 46.949 16.559 46.999 ;
		LAYER M4 ;
		RECT 14.581 47.705 16.559 47.755 ;
		LAYER M4 ;
		RECT 14.581 48.965 16.559 49.015 ;
		LAYER M4 ;
		RECT 14.581 49.721 16.559 49.771 ;
		LAYER M4 ;
		RECT 14.581 50.981 16.559 51.031 ;
		LAYER M4 ;
		RECT 14.581 51.737 16.559 51.787 ;
		LAYER M4 ;
		RECT 14.581 52.997 16.559 53.047 ;
		LAYER M4 ;
		RECT 14.581 53.753 16.559 53.803 ;
		LAYER M4 ;
		RECT 14.581 55.013 16.559 55.063 ;
		LAYER M4 ;
		RECT 14.581 55.769 16.559 55.819 ;
		LAYER M4 ;
		RECT 14.581 57.029 16.559 57.079 ;
		LAYER M4 ;
		RECT 14.581 57.785 16.559 57.835 ;
		LAYER M4 ;
		RECT 14.581 59.045 16.559 59.095 ;
		LAYER M4 ;
		RECT 14.581 59.801 16.559 59.851 ;
		LAYER M4 ;
		RECT 14.581 61.061 16.559 61.111 ;
		LAYER M4 ;
		RECT 14.581 61.817 16.559 61.867 ;
		LAYER M4 ;
		RECT 14.581 63.077 16.559 63.127 ;
		LAYER M4 ;
		RECT 14.581 63.833 16.559 63.883 ;
		LAYER M4 ;
		RECT 14.581 65.093 16.559 65.143 ;
		LAYER M4 ;
		RECT 14.581 78.713 16.559 78.763 ;
		LAYER M4 ;
		RECT 14.581 79.973 16.559 80.023 ;
		LAYER M4 ;
		RECT 14.581 80.729 16.559 80.779 ;
		LAYER M4 ;
		RECT 14.581 81.989 16.559 82.039 ;
		LAYER M4 ;
		RECT 14.581 82.745 16.559 82.795 ;
		LAYER M4 ;
		RECT 14.581 84.005 16.559 84.055 ;
		LAYER M4 ;
		RECT 14.581 84.761 16.559 84.811 ;
		LAYER M4 ;
		RECT 14.581 86.021 16.559 86.071 ;
		LAYER M4 ;
		RECT 14.581 86.777 16.559 86.827 ;
		LAYER M4 ;
		RECT 14.581 88.037 16.559 88.087 ;
		LAYER M4 ;
		RECT 14.581 88.793 16.559 88.843 ;
		LAYER M4 ;
		RECT 14.581 90.053 16.559 90.103 ;
		LAYER M4 ;
		RECT 14.581 90.809 16.559 90.859 ;
		LAYER M4 ;
		RECT 14.581 92.069 16.559 92.119 ;
		LAYER M4 ;
		RECT 14.581 92.825 16.559 92.875 ;
		LAYER M4 ;
		RECT 14.581 94.085 16.559 94.135 ;
		LAYER M4 ;
		RECT 14.581 94.841 16.559 94.891 ;
		LAYER M4 ;
		RECT 14.581 96.101 16.559 96.151 ;
		LAYER M4 ;
		RECT 14.581 96.857 16.559 96.907 ;
		LAYER M4 ;
		RECT 14.581 98.117 16.559 98.167 ;
		LAYER M4 ;
		RECT 14.581 98.873 16.559 98.923 ;
		LAYER M4 ;
		RECT 14.581 100.133 16.559 100.183 ;
		LAYER M4 ;
		RECT 14.581 100.889 16.559 100.939 ;
		LAYER M4 ;
		RECT 14.581 102.149 16.559 102.199 ;
		LAYER M4 ;
		RECT 14.581 102.905 16.559 102.955 ;
		LAYER M4 ;
		RECT 14.581 104.165 16.559 104.215 ;
		LAYER M4 ;
		RECT 14.581 104.921 16.559 104.971 ;
		LAYER M4 ;
		RECT 14.581 106.181 16.559 106.231 ;
		LAYER M4 ;
		RECT 14.581 106.937 16.559 106.987 ;
		LAYER M4 ;
		RECT 14.581 108.197 16.559 108.247 ;
		LAYER M4 ;
		RECT 14.581 108.953 16.559 109.003 ;
		LAYER M4 ;
		RECT 14.581 110.213 16.559 110.263 ;
		LAYER M4 ;
		RECT 14.581 110.969 16.559 111.019 ;
		LAYER M4 ;
		RECT 14.581 112.229 16.559 112.279 ;
		LAYER M4 ;
		RECT 14.581 112.985 16.559 113.035 ;
		LAYER M4 ;
		RECT 14.581 114.245 16.559 114.295 ;
		LAYER M4 ;
		RECT 14.581 115.001 16.559 115.051 ;
		LAYER M4 ;
		RECT 14.581 116.261 16.559 116.311 ;
		LAYER M4 ;
		RECT 14.581 117.017 16.559 117.067 ;
		LAYER M4 ;
		RECT 14.581 118.277 16.559 118.327 ;
		LAYER M4 ;
		RECT 14.581 119.033 16.559 119.083 ;
		LAYER M4 ;
		RECT 14.581 120.293 16.559 120.343 ;
		LAYER M4 ;
		RECT 14.581 121.049 16.559 121.099 ;
		LAYER M4 ;
		RECT 14.581 122.309 16.559 122.359 ;
		LAYER M4 ;
		RECT 14.581 123.065 16.559 123.115 ;
		LAYER M4 ;
		RECT 14.581 124.325 16.559 124.375 ;
		LAYER M4 ;
		RECT 14.581 125.081 16.559 125.131 ;
		LAYER M4 ;
		RECT 14.581 126.341 16.559 126.391 ;
		LAYER M4 ;
		RECT 14.581 127.097 16.559 127.147 ;
		LAYER M4 ;
		RECT 14.581 128.357 16.559 128.407 ;
		LAYER M4 ;
		RECT 14.581 129.113 16.559 129.163 ;
		LAYER M4 ;
		RECT 14.581 130.373 16.559 130.423 ;
		LAYER M4 ;
		RECT 14.581 131.129 16.559 131.179 ;
		LAYER M4 ;
		RECT 14.581 132.389 16.559 132.439 ;
		LAYER M4 ;
		RECT 14.581 133.145 16.559 133.195 ;
		LAYER M4 ;
		RECT 14.581 134.405 16.559 134.455 ;
		LAYER M4 ;
		RECT 14.581 135.161 16.559 135.211 ;
		LAYER M4 ;
		RECT 14.581 136.421 16.559 136.471 ;
		LAYER M4 ;
		RECT 14.581 137.177 16.559 137.227 ;
		LAYER M4 ;
		RECT 14.581 138.437 16.559 138.487 ;
		LAYER M4 ;
		RECT 14.581 139.193 16.559 139.243 ;
		LAYER M4 ;
		RECT 14.581 140.453 16.559 140.503 ;
		LAYER M4 ;
		RECT 14.581 141.209 16.559 141.259 ;
		LAYER M4 ;
		RECT 14.581 142.469 16.559 142.519 ;
		LAYER M4 ;
		RECT 15.757 1.589 16.649 1.639 ;
		LAYER M4 ;
		RECT 15.757 2.343 16.649 2.393 ;
		LAYER M4 ;
		RECT 15.757 3.605 16.649 3.655 ;
		LAYER M4 ;
		RECT 15.757 4.359 16.649 4.409 ;
		LAYER M4 ;
		RECT 15.757 5.621 16.649 5.671 ;
		LAYER M4 ;
		RECT 15.757 6.375 16.649 6.425 ;
		LAYER M4 ;
		RECT 15.757 7.637 16.649 7.687 ;
		LAYER M4 ;
		RECT 15.757 8.391 16.649 8.441 ;
		LAYER M4 ;
		RECT 15.757 9.653 16.649 9.703 ;
		LAYER M4 ;
		RECT 15.757 10.407 16.649 10.457 ;
		LAYER M4 ;
		RECT 15.757 11.669 16.649 11.719 ;
		LAYER M4 ;
		RECT 15.757 12.423 16.649 12.473 ;
		LAYER M4 ;
		RECT 15.757 13.685 16.649 13.735 ;
		LAYER M4 ;
		RECT 15.757 14.439 16.649 14.489 ;
		LAYER M4 ;
		RECT 15.757 15.701 16.649 15.751 ;
		LAYER M4 ;
		RECT 15.757 16.455 16.649 16.505 ;
		LAYER M4 ;
		RECT 15.757 17.717 16.649 17.767 ;
		LAYER M4 ;
		RECT 15.757 18.471 16.649 18.521 ;
		LAYER M4 ;
		RECT 15.757 19.733 16.649 19.783 ;
		LAYER M4 ;
		RECT 15.757 20.487 16.649 20.537 ;
		LAYER M4 ;
		RECT 15.757 21.749 16.649 21.799 ;
		LAYER M4 ;
		RECT 15.757 22.503 16.649 22.553 ;
		LAYER M4 ;
		RECT 15.757 23.765 16.649 23.815 ;
		LAYER M4 ;
		RECT 15.757 24.519 16.649 24.569 ;
		LAYER M4 ;
		RECT 15.757 25.781 16.649 25.831 ;
		LAYER M4 ;
		RECT 15.757 26.535 16.649 26.585 ;
		LAYER M4 ;
		RECT 15.757 27.797 16.649 27.847 ;
		LAYER M4 ;
		RECT 15.757 28.551 16.649 28.601 ;
		LAYER M4 ;
		RECT 15.757 29.813 16.649 29.863 ;
		LAYER M4 ;
		RECT 15.757 30.567 16.649 30.617 ;
		LAYER M4 ;
		RECT 15.757 31.829 16.649 31.879 ;
		LAYER M4 ;
		RECT 15.757 32.583 16.649 32.633 ;
		LAYER M4 ;
		RECT 15.757 33.845 16.649 33.895 ;
		LAYER M4 ;
		RECT 15.757 34.599 16.649 34.649 ;
		LAYER M4 ;
		RECT 15.757 35.861 16.649 35.911 ;
		LAYER M4 ;
		RECT 15.757 36.615 16.649 36.665 ;
		LAYER M4 ;
		RECT 15.757 37.877 16.649 37.927 ;
		LAYER M4 ;
		RECT 15.757 38.631 16.649 38.681 ;
		LAYER M4 ;
		RECT 15.757 39.893 16.649 39.943 ;
		LAYER M4 ;
		RECT 15.757 40.647 16.649 40.697 ;
		LAYER M4 ;
		RECT 15.757 41.909 16.649 41.959 ;
		LAYER M4 ;
		RECT 15.757 42.663 16.649 42.713 ;
		LAYER M4 ;
		RECT 15.757 43.925 16.649 43.975 ;
		LAYER M4 ;
		RECT 15.757 44.679 16.649 44.729 ;
		LAYER M4 ;
		RECT 15.757 45.941 16.649 45.991 ;
		LAYER M4 ;
		RECT 15.757 46.695 16.649 46.745 ;
		LAYER M4 ;
		RECT 15.757 47.957 16.649 48.007 ;
		LAYER M4 ;
		RECT 15.757 48.711 16.649 48.761 ;
		LAYER M4 ;
		RECT 15.757 49.973 16.649 50.023 ;
		LAYER M4 ;
		RECT 15.757 50.727 16.649 50.777 ;
		LAYER M4 ;
		RECT 15.757 51.989 16.649 52.039 ;
		LAYER M4 ;
		RECT 15.757 52.743 16.649 52.793 ;
		LAYER M4 ;
		RECT 15.757 54.005 16.649 54.055 ;
		LAYER M4 ;
		RECT 15.757 54.759 16.649 54.809 ;
		LAYER M4 ;
		RECT 15.757 56.021 16.649 56.071 ;
		LAYER M4 ;
		RECT 15.757 56.775 16.649 56.825 ;
		LAYER M4 ;
		RECT 15.757 58.037 16.649 58.087 ;
		LAYER M4 ;
		RECT 15.757 58.791 16.649 58.841 ;
		LAYER M4 ;
		RECT 15.757 60.053 16.649 60.103 ;
		LAYER M4 ;
		RECT 15.757 60.807 16.649 60.857 ;
		LAYER M4 ;
		RECT 15.757 62.069 16.649 62.119 ;
		LAYER M4 ;
		RECT 15.757 62.823 16.649 62.873 ;
		LAYER M4 ;
		RECT 15.757 64.085 16.649 64.135 ;
		LAYER M4 ;
		RECT 15.757 64.839 16.649 64.889 ;
		LAYER M4 ;
		RECT 15.757 78.965 16.649 79.015 ;
		LAYER M4 ;
		RECT 15.757 79.719 16.649 79.769 ;
		LAYER M4 ;
		RECT 15.757 80.981 16.649 81.031 ;
		LAYER M4 ;
		RECT 15.757 81.735 16.649 81.785 ;
		LAYER M4 ;
		RECT 15.757 82.997 16.649 83.047 ;
		LAYER M4 ;
		RECT 15.757 83.751 16.649 83.801 ;
		LAYER M4 ;
		RECT 15.757 85.013 16.649 85.063 ;
		LAYER M4 ;
		RECT 15.757 85.767 16.649 85.817 ;
		LAYER M4 ;
		RECT 15.757 87.029 16.649 87.079 ;
		LAYER M4 ;
		RECT 15.757 87.783 16.649 87.833 ;
		LAYER M4 ;
		RECT 15.757 89.045 16.649 89.095 ;
		LAYER M4 ;
		RECT 15.757 89.799 16.649 89.849 ;
		LAYER M4 ;
		RECT 15.757 91.061 16.649 91.111 ;
		LAYER M4 ;
		RECT 15.757 91.815 16.649 91.865 ;
		LAYER M4 ;
		RECT 15.757 93.077 16.649 93.127 ;
		LAYER M4 ;
		RECT 15.757 93.831 16.649 93.881 ;
		LAYER M4 ;
		RECT 15.757 95.093 16.649 95.143 ;
		LAYER M4 ;
		RECT 15.757 95.847 16.649 95.897 ;
		LAYER M4 ;
		RECT 15.757 97.109 16.649 97.159 ;
		LAYER M4 ;
		RECT 15.757 97.863 16.649 97.913 ;
		LAYER M4 ;
		RECT 15.757 99.125 16.649 99.175 ;
		LAYER M4 ;
		RECT 15.757 99.879 16.649 99.929 ;
		LAYER M4 ;
		RECT 15.757 101.141 16.649 101.191 ;
		LAYER M4 ;
		RECT 15.757 101.895 16.649 101.945 ;
		LAYER M4 ;
		RECT 15.757 103.157 16.649 103.207 ;
		LAYER M4 ;
		RECT 15.757 103.911 16.649 103.961 ;
		LAYER M4 ;
		RECT 15.757 105.173 16.649 105.223 ;
		LAYER M4 ;
		RECT 15.757 105.927 16.649 105.977 ;
		LAYER M4 ;
		RECT 15.757 107.189 16.649 107.239 ;
		LAYER M4 ;
		RECT 15.757 107.943 16.649 107.993 ;
		LAYER M4 ;
		RECT 15.757 109.205 16.649 109.255 ;
		LAYER M4 ;
		RECT 15.757 109.959 16.649 110.009 ;
		LAYER M4 ;
		RECT 15.757 111.221 16.649 111.271 ;
		LAYER M4 ;
		RECT 15.757 111.975 16.649 112.025 ;
		LAYER M4 ;
		RECT 15.757 113.237 16.649 113.287 ;
		LAYER M4 ;
		RECT 15.757 113.991 16.649 114.041 ;
		LAYER M4 ;
		RECT 15.757 115.253 16.649 115.303 ;
		LAYER M4 ;
		RECT 15.757 116.007 16.649 116.057 ;
		LAYER M4 ;
		RECT 15.757 117.269 16.649 117.319 ;
		LAYER M4 ;
		RECT 15.757 118.023 16.649 118.073 ;
		LAYER M4 ;
		RECT 15.757 119.285 16.649 119.335 ;
		LAYER M4 ;
		RECT 15.757 120.039 16.649 120.089 ;
		LAYER M4 ;
		RECT 15.757 121.301 16.649 121.351 ;
		LAYER M4 ;
		RECT 15.757 122.055 16.649 122.105 ;
		LAYER M4 ;
		RECT 15.757 123.317 16.649 123.367 ;
		LAYER M4 ;
		RECT 15.757 124.071 16.649 124.121 ;
		LAYER M4 ;
		RECT 15.757 125.333 16.649 125.383 ;
		LAYER M4 ;
		RECT 15.757 126.087 16.649 126.137 ;
		LAYER M4 ;
		RECT 15.757 127.349 16.649 127.399 ;
		LAYER M4 ;
		RECT 15.757 128.103 16.649 128.153 ;
		LAYER M4 ;
		RECT 15.757 129.365 16.649 129.415 ;
		LAYER M4 ;
		RECT 15.757 130.119 16.649 130.169 ;
		LAYER M4 ;
		RECT 15.757 131.381 16.649 131.431 ;
		LAYER M4 ;
		RECT 15.757 132.135 16.649 132.185 ;
		LAYER M4 ;
		RECT 15.757 133.397 16.649 133.447 ;
		LAYER M4 ;
		RECT 15.757 134.151 16.649 134.201 ;
		LAYER M4 ;
		RECT 15.757 135.413 16.649 135.463 ;
		LAYER M4 ;
		RECT 15.757 136.167 16.649 136.217 ;
		LAYER M4 ;
		RECT 15.757 137.429 16.649 137.479 ;
		LAYER M4 ;
		RECT 15.757 138.183 16.649 138.233 ;
		LAYER M4 ;
		RECT 15.757 139.445 16.649 139.495 ;
		LAYER M4 ;
		RECT 15.757 140.199 16.649 140.249 ;
		LAYER M4 ;
		RECT 15.757 141.461 16.649 141.511 ;
		LAYER M4 ;
		RECT 15.757 142.215 16.649 142.265 ;
		LAYER VIA1 ;
		RECT 0.000 0.000 25.745 143.856 ;
		LAYER VIA2 ;
		RECT 0.000 0.000 25.745 143.856 ;
	END
END TS1N16ADFPCLLLVTA128X64M4SWSHOD_tag_array

END LIBRARY
